VERSION 5.8 ;
BUSBITCHARS "[]" ;
DIVIDERCHAR "/" ;
UNITS
    DATABASE MICRONS 1000 ;
END UNITS

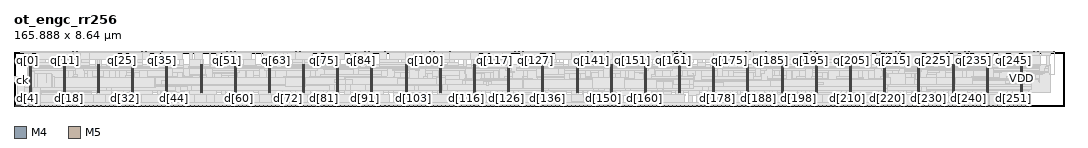
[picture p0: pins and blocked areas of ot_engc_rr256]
MACRO ot_engc_rr256
  FOREIGN ot_engc_rr256 0 0 ;
  CLASS BLOCK ;
  SIZE 165.888 BY 8.64 ;
  PIN ck
    DIRECTION INPUT ;
    USE SIGNAL ;
    PORT
      LAYER M4 ;
        RECT  0 4.032 0.084 4.056 ;
    END
  END ck
  PIN d[0]
    DIRECTION INPUT ;
    USE SIGNAL ;
    PORT
      LAYER M5 ;
        RECT  0.288 0 0.312 0.084 ;
    END
  END d[0]
  PIN d[100]
    DIRECTION INPUT ;
    USE SIGNAL ;
    PORT
      LAYER M5 ;
        RECT  61.152 0 61.176 0.084 ;
    END
  END d[100]
  PIN d[101]
    DIRECTION INPUT ;
    USE SIGNAL ;
    PORT
      LAYER M5 ;
        RECT  61.824 0 61.848 0.084 ;
    END
  END d[101]
  PIN d[102]
    DIRECTION INPUT ;
    USE SIGNAL ;
    PORT
      LAYER M5 ;
        RECT  62.448 0 62.472 0.084 ;
    END
  END d[102]
  PIN d[103]
    DIRECTION INPUT ;
    USE SIGNAL ;
    PORT
      LAYER M5 ;
        RECT  63.072 0 63.096 0.084 ;
    END
  END d[103]
  PIN d[104]
    DIRECTION INPUT ;
    USE SIGNAL ;
    PORT
      LAYER M5 ;
        RECT  63.744 0 63.768 0.084 ;
    END
  END d[104]
  PIN d[105]
    DIRECTION INPUT ;
    USE SIGNAL ;
    PORT
      LAYER M5 ;
        RECT  64.368 0 64.392 0.084 ;
    END
  END d[105]
  PIN d[106]
    DIRECTION INPUT ;
    USE SIGNAL ;
    PORT
      LAYER M5 ;
        RECT  64.992 0 65.016 0.084 ;
    END
  END d[106]
  PIN d[107]
    DIRECTION INPUT ;
    USE SIGNAL ;
    PORT
      LAYER M5 ;
        RECT  65.664 0 65.688 0.084 ;
    END
  END d[107]
  PIN d[108]
    DIRECTION INPUT ;
    USE SIGNAL ;
    PORT
      LAYER M5 ;
        RECT  66.288 0 66.312 0.084 ;
    END
  END d[108]
  PIN d[109]
    DIRECTION INPUT ;
    USE SIGNAL ;
    PORT
      LAYER M5 ;
        RECT  66.912 0 66.936 0.084 ;
    END
  END d[109]
  PIN d[10]
    DIRECTION INPUT ;
    USE SIGNAL ;
    PORT
      LAYER M5 ;
        RECT  3.504 0 3.528 0.084 ;
    END
  END d[10]
  PIN d[110]
    DIRECTION INPUT ;
    USE SIGNAL ;
    PORT
      LAYER M5 ;
        RECT  67.584 0 67.608 0.084 ;
    END
  END d[110]
  PIN d[111]
    DIRECTION INPUT ;
    USE SIGNAL ;
    PORT
      LAYER M5 ;
        RECT  68.208 0 68.232 0.084 ;
    END
  END d[111]
  PIN d[112]
    DIRECTION INPUT ;
    USE SIGNAL ;
    PORT
      LAYER M5 ;
        RECT  68.832 0 68.856 0.084 ;
    END
  END d[112]
  PIN d[113]
    DIRECTION INPUT ;
    USE SIGNAL ;
    PORT
      LAYER M5 ;
        RECT  69.504 0 69.528 0.084 ;
    END
  END d[113]
  PIN d[114]
    DIRECTION INPUT ;
    USE SIGNAL ;
    PORT
      LAYER M5 ;
        RECT  70.128 0 70.152 0.084 ;
    END
  END d[114]
  PIN d[115]
    DIRECTION INPUT ;
    USE SIGNAL ;
    PORT
      LAYER M5 ;
        RECT  70.752 0 70.776 0.084 ;
    END
  END d[115]
  PIN d[116]
    DIRECTION INPUT ;
    USE SIGNAL ;
    PORT
      LAYER M5 ;
        RECT  71.424 0 71.448 0.084 ;
    END
  END d[116]
  PIN d[117]
    DIRECTION INPUT ;
    USE SIGNAL ;
    PORT
      LAYER M5 ;
        RECT  72.048 0 72.072 0.084 ;
    END
  END d[117]
  PIN d[118]
    DIRECTION INPUT ;
    USE SIGNAL ;
    PORT
      LAYER M5 ;
        RECT  72.672 0 72.696 0.084 ;
    END
  END d[118]
  PIN d[119]
    DIRECTION INPUT ;
    USE SIGNAL ;
    PORT
      LAYER M5 ;
        RECT  73.344 0 73.368 0.084 ;
    END
  END d[119]
  PIN d[11]
    DIRECTION INPUT ;
    USE SIGNAL ;
    PORT
      LAYER M5 ;
        RECT  4.128 0 4.152 0.084 ;
    END
  END d[11]
  PIN d[120]
    DIRECTION INPUT ;
    USE SIGNAL ;
    PORT
      LAYER M5 ;
        RECT  73.968 0 73.992 0.084 ;
    END
  END d[120]
  PIN d[121]
    DIRECTION INPUT ;
    USE SIGNAL ;
    PORT
      LAYER M5 ;
        RECT  74.592 0 74.616 0.084 ;
    END
  END d[121]
  PIN d[122]
    DIRECTION INPUT ;
    USE SIGNAL ;
    PORT
      LAYER M5 ;
        RECT  75.264 0 75.288 0.084 ;
    END
  END d[122]
  PIN d[123]
    DIRECTION INPUT ;
    USE SIGNAL ;
    PORT
      LAYER M5 ;
        RECT  75.888 0 75.912 0.084 ;
    END
  END d[123]
  PIN d[124]
    DIRECTION INPUT ;
    USE SIGNAL ;
    PORT
      LAYER M5 ;
        RECT  76.512 0 76.536 0.084 ;
    END
  END d[124]
  PIN d[125]
    DIRECTION INPUT ;
    USE SIGNAL ;
    PORT
      LAYER M5 ;
        RECT  77.184 0 77.208 0.084 ;
    END
  END d[125]
  PIN d[126]
    DIRECTION INPUT ;
    USE SIGNAL ;
    PORT
      LAYER M5 ;
        RECT  77.808 0 77.832 0.084 ;
    END
  END d[126]
  PIN d[127]
    DIRECTION INPUT ;
    USE SIGNAL ;
    PORT
      LAYER M5 ;
        RECT  78.432 0 78.456 0.084 ;
    END
  END d[127]
  PIN d[128]
    DIRECTION INPUT ;
    USE SIGNAL ;
    PORT
      LAYER M5 ;
        RECT  79.104 0 79.128 0.084 ;
    END
  END d[128]
  PIN d[129]
    DIRECTION INPUT ;
    USE SIGNAL ;
    PORT
      LAYER M5 ;
        RECT  79.728 0 79.752 0.084 ;
    END
  END d[129]
  PIN d[12]
    DIRECTION INPUT ;
    USE SIGNAL ;
    PORT
      LAYER M5 ;
        RECT  4.8 0 4.824 0.084 ;
    END
  END d[12]
  PIN d[130]
    DIRECTION INPUT ;
    USE SIGNAL ;
    PORT
      LAYER M5 ;
        RECT  80.352 0 80.376 0.084 ;
    END
  END d[130]
  PIN d[131]
    DIRECTION INPUT ;
    USE SIGNAL ;
    PORT
      LAYER M5 ;
        RECT  81.024 0 81.048 0.084 ;
    END
  END d[131]
  PIN d[132]
    DIRECTION INPUT ;
    USE SIGNAL ;
    PORT
      LAYER M5 ;
        RECT  81.648 0 81.672 0.084 ;
    END
  END d[132]
  PIN d[133]
    DIRECTION INPUT ;
    USE SIGNAL ;
    PORT
      LAYER M5 ;
        RECT  82.272 0 82.296 0.084 ;
    END
  END d[133]
  PIN d[134]
    DIRECTION INPUT ;
    USE SIGNAL ;
    PORT
      LAYER M5 ;
        RECT  82.944 0 82.968 0.084 ;
    END
  END d[134]
  PIN d[135]
    DIRECTION INPUT ;
    USE SIGNAL ;
    PORT
      LAYER M5 ;
        RECT  83.568 0 83.592 0.084 ;
    END
  END d[135]
  PIN d[136]
    DIRECTION INPUT ;
    USE SIGNAL ;
    PORT
      LAYER M5 ;
        RECT  84.24 0 84.264 0.084 ;
    END
  END d[136]
  PIN d[137]
    DIRECTION INPUT ;
    USE SIGNAL ;
    PORT
      LAYER M5 ;
        RECT  84.864 0 84.888 0.084 ;
    END
  END d[137]
  PIN d[138]
    DIRECTION INPUT ;
    USE SIGNAL ;
    PORT
      LAYER M5 ;
        RECT  85.488 0 85.512 0.084 ;
    END
  END d[138]
  PIN d[139]
    DIRECTION INPUT ;
    USE SIGNAL ;
    PORT
      LAYER M5 ;
        RECT  86.16 0 86.184 0.084 ;
    END
  END d[139]
  PIN d[13]
    DIRECTION INPUT ;
    USE SIGNAL ;
    PORT
      LAYER M5 ;
        RECT  5.424 0 5.448 0.084 ;
    END
  END d[13]
  PIN d[140]
    DIRECTION INPUT ;
    USE SIGNAL ;
    PORT
      LAYER M5 ;
        RECT  86.784 0 86.808 0.084 ;
    END
  END d[140]
  PIN d[141]
    DIRECTION INPUT ;
    USE SIGNAL ;
    PORT
      LAYER M5 ;
        RECT  87.408 0 87.432 0.084 ;
    END
  END d[141]
  PIN d[142]
    DIRECTION INPUT ;
    USE SIGNAL ;
    PORT
      LAYER M5 ;
        RECT  88.08 0 88.104 0.084 ;
    END
  END d[142]
  PIN d[143]
    DIRECTION INPUT ;
    USE SIGNAL ;
    PORT
      LAYER M5 ;
        RECT  88.704 0 88.728 0.084 ;
    END
  END d[143]
  PIN d[144]
    DIRECTION INPUT ;
    USE SIGNAL ;
    PORT
      LAYER M5 ;
        RECT  89.328 0 89.352 0.084 ;
    END
  END d[144]
  PIN d[145]
    DIRECTION INPUT ;
    USE SIGNAL ;
    PORT
      LAYER M5 ;
        RECT  90 0 90.024 0.084 ;
    END
  END d[145]
  PIN d[146]
    DIRECTION INPUT ;
    USE SIGNAL ;
    PORT
      LAYER M5 ;
        RECT  90.624 0 90.648 0.084 ;
    END
  END d[146]
  PIN d[147]
    DIRECTION INPUT ;
    USE SIGNAL ;
    PORT
      LAYER M5 ;
        RECT  91.248 0 91.272 0.084 ;
    END
  END d[147]
  PIN d[148]
    DIRECTION INPUT ;
    USE SIGNAL ;
    PORT
      LAYER M5 ;
        RECT  91.92 0 91.944 0.084 ;
    END
  END d[148]
  PIN d[149]
    DIRECTION INPUT ;
    USE SIGNAL ;
    PORT
      LAYER M5 ;
        RECT  92.544 0 92.568 0.084 ;
    END
  END d[149]
  PIN d[14]
    DIRECTION INPUT ;
    USE SIGNAL ;
    PORT
      LAYER M5 ;
        RECT  6.048 0 6.072 0.084 ;
    END
  END d[14]
  PIN d[150]
    DIRECTION INPUT ;
    USE SIGNAL ;
    PORT
      LAYER M5 ;
        RECT  93.168 0 93.192 0.084 ;
    END
  END d[150]
  PIN d[151]
    DIRECTION INPUT ;
    USE SIGNAL ;
    PORT
      LAYER M5 ;
        RECT  93.84 0 93.864 0.084 ;
    END
  END d[151]
  PIN d[152]
    DIRECTION INPUT ;
    USE SIGNAL ;
    PORT
      LAYER M5 ;
        RECT  94.464 0 94.488 0.084 ;
    END
  END d[152]
  PIN d[153]
    DIRECTION INPUT ;
    USE SIGNAL ;
    PORT
      LAYER M5 ;
        RECT  95.088 0 95.112 0.084 ;
    END
  END d[153]
  PIN d[154]
    DIRECTION INPUT ;
    USE SIGNAL ;
    PORT
      LAYER M5 ;
        RECT  95.76 0 95.784 0.084 ;
    END
  END d[154]
  PIN d[155]
    DIRECTION INPUT ;
    USE SIGNAL ;
    PORT
      LAYER M5 ;
        RECT  96.384 0 96.408 0.084 ;
    END
  END d[155]
  PIN d[156]
    DIRECTION INPUT ;
    USE SIGNAL ;
    PORT
      LAYER M5 ;
        RECT  97.008 0 97.032 0.084 ;
    END
  END d[156]
  PIN d[157]
    DIRECTION INPUT ;
    USE SIGNAL ;
    PORT
      LAYER M5 ;
        RECT  97.68 0 97.704 0.084 ;
    END
  END d[157]
  PIN d[158]
    DIRECTION INPUT ;
    USE SIGNAL ;
    PORT
      LAYER M5 ;
        RECT  98.304 0 98.328 0.084 ;
    END
  END d[158]
  PIN d[159]
    DIRECTION INPUT ;
    USE SIGNAL ;
    PORT
      LAYER M5 ;
        RECT  98.976 0 99 0.084 ;
    END
  END d[159]
  PIN d[15]
    DIRECTION INPUT ;
    USE SIGNAL ;
    PORT
      LAYER M5 ;
        RECT  6.72 0 6.744 0.084 ;
    END
  END d[15]
  PIN d[160]
    DIRECTION INPUT ;
    USE SIGNAL ;
    PORT
      LAYER M5 ;
        RECT  99.552 0 99.576 0.084 ;
    END
  END d[160]
  PIN d[161]
    DIRECTION INPUT ;
    USE SIGNAL ;
    PORT
      LAYER M5 ;
        RECT  100.224 0 100.248 0.084 ;
    END
  END d[161]
  PIN d[162]
    DIRECTION INPUT ;
    USE SIGNAL ;
    PORT
      LAYER M5 ;
        RECT  100.848 0 100.872 0.084 ;
    END
  END d[162]
  PIN d[163]
    DIRECTION INPUT ;
    USE SIGNAL ;
    PORT
      LAYER M5 ;
        RECT  101.472 0 101.496 0.084 ;
    END
  END d[163]
  PIN d[164]
    DIRECTION INPUT ;
    USE SIGNAL ;
    PORT
      LAYER M5 ;
        RECT  102.144 0 102.168 0.084 ;
    END
  END d[164]
  PIN d[165]
    DIRECTION INPUT ;
    USE SIGNAL ;
    PORT
      LAYER M5 ;
        RECT  102.768 0 102.792 0.084 ;
    END
  END d[165]
  PIN d[166]
    DIRECTION INPUT ;
    USE SIGNAL ;
    PORT
      LAYER M5 ;
        RECT  103.392 0 103.416 0.084 ;
    END
  END d[166]
  PIN d[167]
    DIRECTION INPUT ;
    USE SIGNAL ;
    PORT
      LAYER M5 ;
        RECT  104.064 0 104.088 0.084 ;
    END
  END d[167]
  PIN d[168]
    DIRECTION INPUT ;
    USE SIGNAL ;
    PORT
      LAYER M5 ;
        RECT  104.688 0 104.712 0.084 ;
    END
  END d[168]
  PIN d[169]
    DIRECTION INPUT ;
    USE SIGNAL ;
    PORT
      LAYER M5 ;
        RECT  105.312 0 105.336 0.084 ;
    END
  END d[169]
  PIN d[16]
    DIRECTION INPUT ;
    USE SIGNAL ;
    PORT
      LAYER M5 ;
        RECT  7.344 0 7.368 0.084 ;
    END
  END d[16]
  PIN d[170]
    DIRECTION INPUT ;
    USE SIGNAL ;
    PORT
      LAYER M5 ;
        RECT  105.984 0 106.008 0.084 ;
    END
  END d[170]
  PIN d[171]
    DIRECTION INPUT ;
    USE SIGNAL ;
    PORT
      LAYER M5 ;
        RECT  106.608 0 106.632 0.084 ;
    END
  END d[171]
  PIN d[172]
    DIRECTION INPUT ;
    USE SIGNAL ;
    PORT
      LAYER M5 ;
        RECT  107.232 0 107.256 0.084 ;
    END
  END d[172]
  PIN d[173]
    DIRECTION INPUT ;
    USE SIGNAL ;
    PORT
      LAYER M5 ;
        RECT  107.904 0 107.928 0.084 ;
    END
  END d[173]
  PIN d[174]
    DIRECTION INPUT ;
    USE SIGNAL ;
    PORT
      LAYER M5 ;
        RECT  108.528 0 108.552 0.084 ;
    END
  END d[174]
  PIN d[175]
    DIRECTION INPUT ;
    USE SIGNAL ;
    PORT
      LAYER M5 ;
        RECT  109.152 0 109.176 0.084 ;
    END
  END d[175]
  PIN d[176]
    DIRECTION INPUT ;
    USE SIGNAL ;
    PORT
      LAYER M5 ;
        RECT  109.824 0 109.848 0.084 ;
    END
  END d[176]
  PIN d[177]
    DIRECTION INPUT ;
    USE SIGNAL ;
    PORT
      LAYER M5 ;
        RECT  110.448 0 110.472 0.084 ;
    END
  END d[177]
  PIN d[178]
    DIRECTION INPUT ;
    USE SIGNAL ;
    PORT
      LAYER M5 ;
        RECT  111.168 0 111.192 0.084 ;
    END
  END d[178]
  PIN d[179]
    DIRECTION INPUT ;
    USE SIGNAL ;
    PORT
      LAYER M5 ;
        RECT  111.792 0 111.816 0.084 ;
    END
  END d[179]
  PIN d[17]
    DIRECTION INPUT ;
    USE SIGNAL ;
    PORT
      LAYER M5 ;
        RECT  7.968 0 7.992 0.084 ;
    END
  END d[17]
  PIN d[180]
    DIRECTION INPUT ;
    USE SIGNAL ;
    PORT
      LAYER M5 ;
        RECT  112.416 0 112.44 0.084 ;
    END
  END d[180]
  PIN d[181]
    DIRECTION INPUT ;
    USE SIGNAL ;
    PORT
      LAYER M5 ;
        RECT  113.088 0 113.112 0.084 ;
    END
  END d[181]
  PIN d[182]
    DIRECTION INPUT ;
    USE SIGNAL ;
    PORT
      LAYER M5 ;
        RECT  113.712 0 113.736 0.084 ;
    END
  END d[182]
  PIN d[183]
    DIRECTION INPUT ;
    USE SIGNAL ;
    PORT
      LAYER M5 ;
        RECT  114.336 0 114.36 0.084 ;
    END
  END d[183]
  PIN d[184]
    DIRECTION INPUT ;
    USE SIGNAL ;
    PORT
      LAYER M5 ;
        RECT  115.008 0 115.032 0.084 ;
    END
  END d[184]
  PIN d[185]
    DIRECTION INPUT ;
    USE SIGNAL ;
    PORT
      LAYER M5 ;
        RECT  115.632 0 115.656 0.084 ;
    END
  END d[185]
  PIN d[186]
    DIRECTION INPUT ;
    USE SIGNAL ;
    PORT
      LAYER M5 ;
        RECT  116.256 0 116.28 0.084 ;
    END
  END d[186]
  PIN d[187]
    DIRECTION INPUT ;
    USE SIGNAL ;
    PORT
      LAYER M5 ;
        RECT  116.928 0 116.952 0.084 ;
    END
  END d[187]
  PIN d[188]
    DIRECTION INPUT ;
    USE SIGNAL ;
    PORT
      LAYER M5 ;
        RECT  117.552 0 117.576 0.084 ;
    END
  END d[188]
  PIN d[189]
    DIRECTION INPUT ;
    USE SIGNAL ;
    PORT
      LAYER M5 ;
        RECT  118.176 0 118.2 0.084 ;
    END
  END d[189]
  PIN d[18]
    DIRECTION INPUT ;
    USE SIGNAL ;
    PORT
      LAYER M5 ;
        RECT  8.64 0 8.664 0.084 ;
    END
  END d[18]
  PIN d[190]
    DIRECTION INPUT ;
    USE SIGNAL ;
    PORT
      LAYER M5 ;
        RECT  118.848 0 118.872 0.084 ;
    END
  END d[190]
  PIN d[191]
    DIRECTION INPUT ;
    USE SIGNAL ;
    PORT
      LAYER M5 ;
        RECT  119.472 0 119.496 0.084 ;
    END
  END d[191]
  PIN d[192]
    DIRECTION INPUT ;
    USE SIGNAL ;
    PORT
      LAYER M5 ;
        RECT  120.096 0 120.12 0.084 ;
    END
  END d[192]
  PIN d[193]
    DIRECTION INPUT ;
    USE SIGNAL ;
    PORT
      LAYER M5 ;
        RECT  120.72 0 120.744 0.084 ;
    END
  END d[193]
  PIN d[194]
    DIRECTION INPUT ;
    USE SIGNAL ;
    PORT
      LAYER M5 ;
        RECT  121.392 0 121.416 0.084 ;
    END
  END d[194]
  PIN d[195]
    DIRECTION INPUT ;
    USE SIGNAL ;
    PORT
      LAYER M5 ;
        RECT  122.016 0 122.04 0.084 ;
    END
  END d[195]
  PIN d[196]
    DIRECTION INPUT ;
    USE SIGNAL ;
    PORT
      LAYER M5 ;
        RECT  122.64 0 122.664 0.084 ;
    END
  END d[196]
  PIN d[197]
    DIRECTION INPUT ;
    USE SIGNAL ;
    PORT
      LAYER M5 ;
        RECT  123.312 0 123.336 0.084 ;
    END
  END d[197]
  PIN d[198]
    DIRECTION INPUT ;
    USE SIGNAL ;
    PORT
      LAYER M5 ;
        RECT  123.936 0 123.96 0.084 ;
    END
  END d[198]
  PIN d[199]
    DIRECTION INPUT ;
    USE SIGNAL ;
    PORT
      LAYER M5 ;
        RECT  124.56 0 124.584 0.084 ;
    END
  END d[199]
  PIN d[19]
    DIRECTION INPUT ;
    USE SIGNAL ;
    PORT
      LAYER M5 ;
        RECT  9.264 0 9.288 0.084 ;
    END
  END d[19]
  PIN d[1]
    DIRECTION INPUT ;
    USE SIGNAL ;
    PORT
      LAYER M5 ;
        RECT  0.384 0 0.408 0.084 ;
    END
  END d[1]
  PIN d[200]
    DIRECTION INPUT ;
    USE SIGNAL ;
    PORT
      LAYER M5 ;
        RECT  125.232 0 125.256 0.084 ;
    END
  END d[200]
  PIN d[201]
    DIRECTION INPUT ;
    USE SIGNAL ;
    PORT
      LAYER M5 ;
        RECT  125.856 0 125.88 0.084 ;
    END
  END d[201]
  PIN d[202]
    DIRECTION INPUT ;
    USE SIGNAL ;
    PORT
      LAYER M5 ;
        RECT  126.48 0 126.504 0.084 ;
    END
  END d[202]
  PIN d[203]
    DIRECTION INPUT ;
    USE SIGNAL ;
    PORT
      LAYER M5 ;
        RECT  127.152 0 127.176 0.084 ;
    END
  END d[203]
  PIN d[204]
    DIRECTION INPUT ;
    USE SIGNAL ;
    PORT
      LAYER M5 ;
        RECT  127.776 0 127.8 0.084 ;
    END
  END d[204]
  PIN d[205]
    DIRECTION INPUT ;
    USE SIGNAL ;
    PORT
      LAYER M5 ;
        RECT  128.4 0 128.424 0.084 ;
    END
  END d[205]
  PIN d[206]
    DIRECTION INPUT ;
    USE SIGNAL ;
    PORT
      LAYER M5 ;
        RECT  129.072 0 129.096 0.084 ;
    END
  END d[206]
  PIN d[207]
    DIRECTION INPUT ;
    USE SIGNAL ;
    PORT
      LAYER M5 ;
        RECT  129.696 0 129.72 0.084 ;
    END
  END d[207]
  PIN d[208]
    DIRECTION INPUT ;
    USE SIGNAL ;
    PORT
      LAYER M5 ;
        RECT  130.32 0 130.344 0.084 ;
    END
  END d[208]
  PIN d[209]
    DIRECTION INPUT ;
    USE SIGNAL ;
    PORT
      LAYER M5 ;
        RECT  130.992 0 131.016 0.084 ;
    END
  END d[209]
  PIN d[20]
    DIRECTION INPUT ;
    USE SIGNAL ;
    PORT
      LAYER M5 ;
        RECT  9.888 0 9.912 0.084 ;
    END
  END d[20]
  PIN d[210]
    DIRECTION INPUT ;
    USE SIGNAL ;
    PORT
      LAYER M5 ;
        RECT  131.616 0 131.64 0.084 ;
    END
  END d[210]
  PIN d[211]
    DIRECTION INPUT ;
    USE SIGNAL ;
    PORT
      LAYER M5 ;
        RECT  132.288 0 132.312 0.084 ;
    END
  END d[211]
  PIN d[212]
    DIRECTION INPUT ;
    USE SIGNAL ;
    PORT
      LAYER M5 ;
        RECT  132.912 0 132.936 0.084 ;
    END
  END d[212]
  PIN d[213]
    DIRECTION INPUT ;
    USE SIGNAL ;
    PORT
      LAYER M5 ;
        RECT  133.536 0 133.56 0.084 ;
    END
  END d[213]
  PIN d[214]
    DIRECTION INPUT ;
    USE SIGNAL ;
    PORT
      LAYER M5 ;
        RECT  134.208 0 134.232 0.084 ;
    END
  END d[214]
  PIN d[215]
    DIRECTION INPUT ;
    USE SIGNAL ;
    PORT
      LAYER M5 ;
        RECT  134.832 0 134.856 0.084 ;
    END
  END d[215]
  PIN d[216]
    DIRECTION INPUT ;
    USE SIGNAL ;
    PORT
      LAYER M5 ;
        RECT  135.456 0 135.48 0.084 ;
    END
  END d[216]
  PIN d[217]
    DIRECTION INPUT ;
    USE SIGNAL ;
    PORT
      LAYER M5 ;
        RECT  136.128 0 136.152 0.084 ;
    END
  END d[217]
  PIN d[218]
    DIRECTION INPUT ;
    USE SIGNAL ;
    PORT
      LAYER M5 ;
        RECT  136.752 0 136.776 0.084 ;
    END
  END d[218]
  PIN d[219]
    DIRECTION INPUT ;
    USE SIGNAL ;
    PORT
      LAYER M5 ;
        RECT  137.376 0 137.4 0.084 ;
    END
  END d[219]
  PIN d[21]
    DIRECTION INPUT ;
    USE SIGNAL ;
    PORT
      LAYER M5 ;
        RECT  10.56 0 10.584 0.084 ;
    END
  END d[21]
  PIN d[220]
    DIRECTION INPUT ;
    USE SIGNAL ;
    PORT
      LAYER M5 ;
        RECT  138.048 0 138.072 0.084 ;
    END
  END d[220]
  PIN d[221]
    DIRECTION INPUT ;
    USE SIGNAL ;
    PORT
      LAYER M5 ;
        RECT  138.672 0 138.696 0.084 ;
    END
  END d[221]
  PIN d[222]
    DIRECTION INPUT ;
    USE SIGNAL ;
    PORT
      LAYER M5 ;
        RECT  139.296 0 139.32 0.084 ;
    END
  END d[222]
  PIN d[223]
    DIRECTION INPUT ;
    USE SIGNAL ;
    PORT
      LAYER M5 ;
        RECT  139.968 0 139.992 0.084 ;
    END
  END d[223]
  PIN d[224]
    DIRECTION INPUT ;
    USE SIGNAL ;
    PORT
      LAYER M5 ;
        RECT  140.592 0 140.616 0.084 ;
    END
  END d[224]
  PIN d[225]
    DIRECTION INPUT ;
    USE SIGNAL ;
    PORT
      LAYER M5 ;
        RECT  141.216 0 141.24 0.084 ;
    END
  END d[225]
  PIN d[226]
    DIRECTION INPUT ;
    USE SIGNAL ;
    PORT
      LAYER M5 ;
        RECT  141.888 0 141.912 0.084 ;
    END
  END d[226]
  PIN d[227]
    DIRECTION INPUT ;
    USE SIGNAL ;
    PORT
      LAYER M5 ;
        RECT  142.512 0 142.536 0.084 ;
    END
  END d[227]
  PIN d[228]
    DIRECTION INPUT ;
    USE SIGNAL ;
    PORT
      LAYER M5 ;
        RECT  143.136 0 143.16 0.084 ;
    END
  END d[228]
  PIN d[229]
    DIRECTION INPUT ;
    USE SIGNAL ;
    PORT
      LAYER M5 ;
        RECT  143.808 0 143.832 0.084 ;
    END
  END d[229]
  PIN d[22]
    DIRECTION INPUT ;
    USE SIGNAL ;
    PORT
      LAYER M5 ;
        RECT  11.184 0 11.208 0.084 ;
    END
  END d[22]
  PIN d[230]
    DIRECTION INPUT ;
    USE SIGNAL ;
    PORT
      LAYER M5 ;
        RECT  144.432 0 144.456 0.084 ;
    END
  END d[230]
  PIN d[231]
    DIRECTION INPUT ;
    USE SIGNAL ;
    PORT
      LAYER M5 ;
        RECT  145.056 0 145.08 0.084 ;
    END
  END d[231]
  PIN d[232]
    DIRECTION INPUT ;
    USE SIGNAL ;
    PORT
      LAYER M5 ;
        RECT  145.728 0 145.752 0.084 ;
    END
  END d[232]
  PIN d[233]
    DIRECTION INPUT ;
    USE SIGNAL ;
    PORT
      LAYER M5 ;
        RECT  146.352 0 146.376 0.084 ;
    END
  END d[233]
  PIN d[234]
    DIRECTION INPUT ;
    USE SIGNAL ;
    PORT
      LAYER M5 ;
        RECT  146.976 0 147 0.084 ;
    END
  END d[234]
  PIN d[235]
    DIRECTION INPUT ;
    USE SIGNAL ;
    PORT
      LAYER M5 ;
        RECT  147.648 0 147.672 0.084 ;
    END
  END d[235]
  PIN d[236]
    DIRECTION INPUT ;
    USE SIGNAL ;
    PORT
      LAYER M5 ;
        RECT  148.272 0 148.296 0.084 ;
    END
  END d[236]
  PIN d[237]
    DIRECTION INPUT ;
    USE SIGNAL ;
    PORT
      LAYER M5 ;
        RECT  148.896 0 148.92 0.084 ;
    END
  END d[237]
  PIN d[238]
    DIRECTION INPUT ;
    USE SIGNAL ;
    PORT
      LAYER M5 ;
        RECT  149.568 0 149.592 0.084 ;
    END
  END d[238]
  PIN d[239]
    DIRECTION INPUT ;
    USE SIGNAL ;
    PORT
      LAYER M5 ;
        RECT  150.192 0 150.216 0.084 ;
    END
  END d[239]
  PIN d[23]
    DIRECTION INPUT ;
    USE SIGNAL ;
    PORT
      LAYER M5 ;
        RECT  11.808 0 11.832 0.084 ;
    END
  END d[23]
  PIN d[240]
    DIRECTION INPUT ;
    USE SIGNAL ;
    PORT
      LAYER M5 ;
        RECT  150.816 0 150.84 0.084 ;
    END
  END d[240]
  PIN d[241]
    DIRECTION INPUT ;
    USE SIGNAL ;
    PORT
      LAYER M5 ;
        RECT  151.488 0 151.512 0.084 ;
    END
  END d[241]
  PIN d[242]
    DIRECTION INPUT ;
    USE SIGNAL ;
    PORT
      LAYER M5 ;
        RECT  152.112 0 152.136 0.084 ;
    END
  END d[242]
  PIN d[243]
    DIRECTION INPUT ;
    USE SIGNAL ;
    PORT
      LAYER M5 ;
        RECT  152.736 0 152.76 0.084 ;
    END
  END d[243]
  PIN d[244]
    DIRECTION INPUT ;
    USE SIGNAL ;
    PORT
      LAYER M5 ;
        RECT  153.408 0 153.432 0.084 ;
    END
  END d[244]
  PIN d[245]
    DIRECTION INPUT ;
    USE SIGNAL ;
    PORT
      LAYER M5 ;
        RECT  154.032 0 154.056 0.084 ;
    END
  END d[245]
  PIN d[246]
    DIRECTION INPUT ;
    USE SIGNAL ;
    PORT
      LAYER M5 ;
        RECT  154.656 0 154.68 0.084 ;
    END
  END d[246]
  PIN d[247]
    DIRECTION INPUT ;
    USE SIGNAL ;
    PORT
      LAYER M5 ;
        RECT  155.328 0 155.352 0.084 ;
    END
  END d[247]
  PIN d[248]
    DIRECTION INPUT ;
    USE SIGNAL ;
    PORT
      LAYER M5 ;
        RECT  155.952 0 155.976 0.084 ;
    END
  END d[248]
  PIN d[249]
    DIRECTION INPUT ;
    USE SIGNAL ;
    PORT
      LAYER M5 ;
        RECT  156.576 0 156.6 0.084 ;
    END
  END d[249]
  PIN d[24]
    DIRECTION INPUT ;
    USE SIGNAL ;
    PORT
      LAYER M5 ;
        RECT  12.48 0 12.504 0.084 ;
    END
  END d[24]
  PIN d[250]
    DIRECTION INPUT ;
    USE SIGNAL ;
    PORT
      LAYER M5 ;
        RECT  157.248 0 157.272 0.084 ;
    END
  END d[250]
  PIN d[251]
    DIRECTION INPUT ;
    USE SIGNAL ;
    PORT
      LAYER M5 ;
        RECT  157.872 0 157.896 0.084 ;
    END
  END d[251]
  PIN d[252]
    DIRECTION INPUT ;
    USE SIGNAL ;
    PORT
      LAYER M5 ;
        RECT  158.496 0 158.52 0.084 ;
    END
  END d[252]
  PIN d[253]
    DIRECTION INPUT ;
    USE SIGNAL ;
    PORT
      LAYER M5 ;
        RECT  159.168 0 159.192 0.084 ;
    END
  END d[253]
  PIN d[254]
    DIRECTION INPUT ;
    USE SIGNAL ;
    PORT
      LAYER M5 ;
        RECT  159.792 0 159.816 0.084 ;
    END
  END d[254]
  PIN d[255]
    DIRECTION INPUT ;
    USE SIGNAL ;
    PORT
      LAYER M5 ;
        RECT  160.416 0 160.44 0.084 ;
    END
  END d[255]
  PIN d[25]
    DIRECTION INPUT ;
    USE SIGNAL ;
    PORT
      LAYER M5 ;
        RECT  13.104 0 13.128 0.084 ;
    END
  END d[25]
  PIN d[26]
    DIRECTION INPUT ;
    USE SIGNAL ;
    PORT
      LAYER M5 ;
        RECT  13.728 0 13.752 0.084 ;
    END
  END d[26]
  PIN d[27]
    DIRECTION INPUT ;
    USE SIGNAL ;
    PORT
      LAYER M5 ;
        RECT  14.4 0 14.424 0.084 ;
    END
  END d[27]
  PIN d[28]
    DIRECTION INPUT ;
    USE SIGNAL ;
    PORT
      LAYER M5 ;
        RECT  15.024 0 15.048 0.084 ;
    END
  END d[28]
  PIN d[29]
    DIRECTION INPUT ;
    USE SIGNAL ;
    PORT
      LAYER M5 ;
        RECT  15.648 0 15.672 0.084 ;
    END
  END d[29]
  PIN d[2]
    DIRECTION INPUT ;
    USE SIGNAL ;
    PORT
      LAYER M5 ;
        RECT  0.48 0 0.504 0.084 ;
    END
  END d[2]
  PIN d[30]
    DIRECTION INPUT ;
    USE SIGNAL ;
    PORT
      LAYER M5 ;
        RECT  16.32 0 16.344 0.084 ;
    END
  END d[30]
  PIN d[31]
    DIRECTION INPUT ;
    USE SIGNAL ;
    PORT
      LAYER M5 ;
        RECT  16.944 0 16.968 0.084 ;
    END
  END d[31]
  PIN d[32]
    DIRECTION INPUT ;
    USE SIGNAL ;
    PORT
      LAYER M5 ;
        RECT  17.568 0 17.592 0.084 ;
    END
  END d[32]
  PIN d[33]
    DIRECTION INPUT ;
    USE SIGNAL ;
    PORT
      LAYER M5 ;
        RECT  18.24 0 18.264 0.084 ;
    END
  END d[33]
  PIN d[34]
    DIRECTION INPUT ;
    USE SIGNAL ;
    PORT
      LAYER M5 ;
        RECT  18.864 0 18.888 0.084 ;
    END
  END d[34]
  PIN d[35]
    DIRECTION INPUT ;
    USE SIGNAL ;
    PORT
      LAYER M5 ;
        RECT  19.488 0 19.512 0.084 ;
    END
  END d[35]
  PIN d[36]
    DIRECTION INPUT ;
    USE SIGNAL ;
    PORT
      LAYER M5 ;
        RECT  20.16 0 20.184 0.084 ;
    END
  END d[36]
  PIN d[37]
    DIRECTION INPUT ;
    USE SIGNAL ;
    PORT
      LAYER M5 ;
        RECT  20.784 0 20.808 0.084 ;
    END
  END d[37]
  PIN d[38]
    DIRECTION INPUT ;
    USE SIGNAL ;
    PORT
      LAYER M5 ;
        RECT  21.408 0 21.432 0.084 ;
    END
  END d[38]
  PIN d[39]
    DIRECTION INPUT ;
    USE SIGNAL ;
    PORT
      LAYER M5 ;
        RECT  22.08 0 22.104 0.084 ;
    END
  END d[39]
  PIN d[3]
    DIRECTION INPUT ;
    USE SIGNAL ;
    PORT
      LAYER M5 ;
        RECT  0.576 0 0.6 0.084 ;
    END
  END d[3]
  PIN d[40]
    DIRECTION INPUT ;
    USE SIGNAL ;
    PORT
      LAYER M5 ;
        RECT  22.704 0 22.728 0.084 ;
    END
  END d[40]
  PIN d[41]
    DIRECTION INPUT ;
    USE SIGNAL ;
    PORT
      LAYER M5 ;
        RECT  23.328 0 23.352 0.084 ;
    END
  END d[41]
  PIN d[42]
    DIRECTION INPUT ;
    USE SIGNAL ;
    PORT
      LAYER M5 ;
        RECT  24 0 24.024 0.084 ;
    END
  END d[42]
  PIN d[43]
    DIRECTION INPUT ;
    USE SIGNAL ;
    PORT
      LAYER M5 ;
        RECT  24.624 0 24.648 0.084 ;
    END
  END d[43]
  PIN d[44]
    DIRECTION INPUT ;
    USE SIGNAL ;
    PORT
      LAYER M5 ;
        RECT  25.248 0 25.272 0.084 ;
    END
  END d[44]
  PIN d[45]
    DIRECTION INPUT ;
    USE SIGNAL ;
    PORT
      LAYER M5 ;
        RECT  25.92 0 25.944 0.084 ;
    END
  END d[45]
  PIN d[46]
    DIRECTION INPUT ;
    USE SIGNAL ;
    PORT
      LAYER M5 ;
        RECT  26.544 0 26.568 0.084 ;
    END
  END d[46]
  PIN d[47]
    DIRECTION INPUT ;
    USE SIGNAL ;
    PORT
      LAYER M5 ;
        RECT  27.168 0 27.192 0.084 ;
    END
  END d[47]
  PIN d[48]
    DIRECTION INPUT ;
    USE SIGNAL ;
    PORT
      LAYER M5 ;
        RECT  27.84 0 27.864 0.084 ;
    END
  END d[48]
  PIN d[49]
    DIRECTION INPUT ;
    USE SIGNAL ;
    PORT
      LAYER M5 ;
        RECT  28.464 0 28.488 0.084 ;
    END
  END d[49]
  PIN d[4]
    DIRECTION INPUT ;
    USE SIGNAL ;
    PORT
      LAYER M5 ;
        RECT  0.672 0 0.696 0.084 ;
    END
  END d[4]
  PIN d[50]
    DIRECTION INPUT ;
    USE SIGNAL ;
    PORT
      LAYER M5 ;
        RECT  29.088 0 29.112 0.084 ;
    END
  END d[50]
  PIN d[51]
    DIRECTION INPUT ;
    USE SIGNAL ;
    PORT
      LAYER M5 ;
        RECT  29.76 0 29.784 0.084 ;
    END
  END d[51]
  PIN d[52]
    DIRECTION INPUT ;
    USE SIGNAL ;
    PORT
      LAYER M5 ;
        RECT  30.384 0 30.408 0.084 ;
    END
  END d[52]
  PIN d[53]
    DIRECTION INPUT ;
    USE SIGNAL ;
    PORT
      LAYER M5 ;
        RECT  31.008 0 31.032 0.084 ;
    END
  END d[53]
  PIN d[54]
    DIRECTION INPUT ;
    USE SIGNAL ;
    PORT
      LAYER M5 ;
        RECT  31.68 0 31.704 0.084 ;
    END
  END d[54]
  PIN d[55]
    DIRECTION INPUT ;
    USE SIGNAL ;
    PORT
      LAYER M5 ;
        RECT  32.304 0 32.328 0.084 ;
    END
  END d[55]
  PIN d[56]
    DIRECTION INPUT ;
    USE SIGNAL ;
    PORT
      LAYER M5 ;
        RECT  32.928 0 32.952 0.084 ;
    END
  END d[56]
  PIN d[57]
    DIRECTION INPUT ;
    USE SIGNAL ;
    PORT
      LAYER M5 ;
        RECT  33.6 0 33.624 0.084 ;
    END
  END d[57]
  PIN d[58]
    DIRECTION INPUT ;
    USE SIGNAL ;
    PORT
      LAYER M5 ;
        RECT  34.224 0 34.248 0.084 ;
    END
  END d[58]
  PIN d[59]
    DIRECTION INPUT ;
    USE SIGNAL ;
    PORT
      LAYER M5 ;
        RECT  34.848 0 34.872 0.084 ;
    END
  END d[59]
  PIN d[5]
    DIRECTION INPUT ;
    USE SIGNAL ;
    PORT
      LAYER M5 ;
        RECT  0.768 0 0.792 0.084 ;
    END
  END d[5]
  PIN d[60]
    DIRECTION INPUT ;
    USE SIGNAL ;
    PORT
      LAYER M5 ;
        RECT  35.52 0 35.544 0.084 ;
    END
  END d[60]
  PIN d[61]
    DIRECTION INPUT ;
    USE SIGNAL ;
    PORT
      LAYER M5 ;
        RECT  36.144 0 36.168 0.084 ;
    END
  END d[61]
  PIN d[62]
    DIRECTION INPUT ;
    USE SIGNAL ;
    PORT
      LAYER M5 ;
        RECT  36.768 0 36.792 0.084 ;
    END
  END d[62]
  PIN d[63]
    DIRECTION INPUT ;
    USE SIGNAL ;
    PORT
      LAYER M5 ;
        RECT  37.44 0 37.464 0.084 ;
    END
  END d[63]
  PIN d[64]
    DIRECTION INPUT ;
    USE SIGNAL ;
    PORT
      LAYER M5 ;
        RECT  38.112 0 38.136 0.084 ;
    END
  END d[64]
  PIN d[65]
    DIRECTION INPUT ;
    USE SIGNAL ;
    PORT
      LAYER M5 ;
        RECT  38.736 0 38.76 0.084 ;
    END
  END d[65]
  PIN d[66]
    DIRECTION INPUT ;
    USE SIGNAL ;
    PORT
      LAYER M5 ;
        RECT  39.36 0 39.384 0.084 ;
    END
  END d[66]
  PIN d[67]
    DIRECTION INPUT ;
    USE SIGNAL ;
    PORT
      LAYER M5 ;
        RECT  40.032 0 40.056 0.084 ;
    END
  END d[67]
  PIN d[68]
    DIRECTION INPUT ;
    USE SIGNAL ;
    PORT
      LAYER M5 ;
        RECT  40.656 0 40.68 0.084 ;
    END
  END d[68]
  PIN d[69]
    DIRECTION INPUT ;
    USE SIGNAL ;
    PORT
      LAYER M5 ;
        RECT  41.28 0 41.304 0.084 ;
    END
  END d[69]
  PIN d[6]
    DIRECTION INPUT ;
    USE SIGNAL ;
    PORT
      LAYER M5 ;
        RECT  0.96 0 0.984 0.084 ;
    END
  END d[6]
  PIN d[70]
    DIRECTION INPUT ;
    USE SIGNAL ;
    PORT
      LAYER M5 ;
        RECT  41.952 0 41.976 0.084 ;
    END
  END d[70]
  PIN d[71]
    DIRECTION INPUT ;
    USE SIGNAL ;
    PORT
      LAYER M5 ;
        RECT  42.576 0 42.6 0.084 ;
    END
  END d[71]
  PIN d[72]
    DIRECTION INPUT ;
    USE SIGNAL ;
    PORT
      LAYER M5 ;
        RECT  43.2 0 43.224 0.084 ;
    END
  END d[72]
  PIN d[73]
    DIRECTION INPUT ;
    USE SIGNAL ;
    PORT
      LAYER M5 ;
        RECT  43.872 0 43.896 0.084 ;
    END
  END d[73]
  PIN d[74]
    DIRECTION INPUT ;
    USE SIGNAL ;
    PORT
      LAYER M5 ;
        RECT  44.496 0 44.52 0.084 ;
    END
  END d[74]
  PIN d[75]
    DIRECTION INPUT ;
    USE SIGNAL ;
    PORT
      LAYER M5 ;
        RECT  45.12 0 45.144 0.084 ;
    END
  END d[75]
  PIN d[76]
    DIRECTION INPUT ;
    USE SIGNAL ;
    PORT
      LAYER M5 ;
        RECT  45.792 0 45.816 0.084 ;
    END
  END d[76]
  PIN d[77]
    DIRECTION INPUT ;
    USE SIGNAL ;
    PORT
      LAYER M5 ;
        RECT  46.416 0 46.44 0.084 ;
    END
  END d[77]
  PIN d[78]
    DIRECTION INPUT ;
    USE SIGNAL ;
    PORT
      LAYER M5 ;
        RECT  47.04 0 47.064 0.084 ;
    END
  END d[78]
  PIN d[79]
    DIRECTION INPUT ;
    USE SIGNAL ;
    PORT
      LAYER M5 ;
        RECT  47.712 0 47.736 0.084 ;
    END
  END d[79]
  PIN d[7]
    DIRECTION INPUT ;
    USE SIGNAL ;
    PORT
      LAYER M5 ;
        RECT  1.584 0 1.608 0.084 ;
    END
  END d[7]
  PIN d[80]
    DIRECTION INPUT ;
    USE SIGNAL ;
    PORT
      LAYER M5 ;
        RECT  48.336 0 48.36 0.084 ;
    END
  END d[80]
  PIN d[81]
    DIRECTION INPUT ;
    USE SIGNAL ;
    PORT
      LAYER M5 ;
        RECT  48.96 0 48.984 0.084 ;
    END
  END d[81]
  PIN d[82]
    DIRECTION INPUT ;
    USE SIGNAL ;
    PORT
      LAYER M5 ;
        RECT  49.632 0 49.656 0.084 ;
    END
  END d[82]
  PIN d[83]
    DIRECTION INPUT ;
    USE SIGNAL ;
    PORT
      LAYER M5 ;
        RECT  50.256 0 50.28 0.084 ;
    END
  END d[83]
  PIN d[84]
    DIRECTION INPUT ;
    USE SIGNAL ;
    PORT
      LAYER M5 ;
        RECT  50.928 0 50.952 0.084 ;
    END
  END d[84]
  PIN d[85]
    DIRECTION INPUT ;
    USE SIGNAL ;
    PORT
      LAYER M5 ;
        RECT  51.552 0 51.576 0.084 ;
    END
  END d[85]
  PIN d[86]
    DIRECTION INPUT ;
    USE SIGNAL ;
    PORT
      LAYER M5 ;
        RECT  52.176 0 52.2 0.084 ;
    END
  END d[86]
  PIN d[87]
    DIRECTION INPUT ;
    USE SIGNAL ;
    PORT
      LAYER M5 ;
        RECT  52.848 0 52.872 0.084 ;
    END
  END d[87]
  PIN d[88]
    DIRECTION INPUT ;
    USE SIGNAL ;
    PORT
      LAYER M5 ;
        RECT  53.472 0 53.496 0.084 ;
    END
  END d[88]
  PIN d[89]
    DIRECTION INPUT ;
    USE SIGNAL ;
    PORT
      LAYER M5 ;
        RECT  54.096 0 54.12 0.084 ;
    END
  END d[89]
  PIN d[8]
    DIRECTION INPUT ;
    USE SIGNAL ;
    PORT
      LAYER M5 ;
        RECT  2.208 0 2.232 0.084 ;
    END
  END d[8]
  PIN d[90]
    DIRECTION INPUT ;
    USE SIGNAL ;
    PORT
      LAYER M5 ;
        RECT  54.768 0 54.792 0.084 ;
    END
  END d[90]
  PIN d[91]
    DIRECTION INPUT ;
    USE SIGNAL ;
    PORT
      LAYER M5 ;
        RECT  55.392 0 55.416 0.084 ;
    END
  END d[91]
  PIN d[92]
    DIRECTION INPUT ;
    USE SIGNAL ;
    PORT
      LAYER M5 ;
        RECT  56.016 0 56.04 0.084 ;
    END
  END d[92]
  PIN d[93]
    DIRECTION INPUT ;
    USE SIGNAL ;
    PORT
      LAYER M5 ;
        RECT  56.688 0 56.712 0.084 ;
    END
  END d[93]
  PIN d[94]
    DIRECTION INPUT ;
    USE SIGNAL ;
    PORT
      LAYER M5 ;
        RECT  57.312 0 57.336 0.084 ;
    END
  END d[94]
  PIN d[95]
    DIRECTION INPUT ;
    USE SIGNAL ;
    PORT
      LAYER M5 ;
        RECT  57.936 0 57.96 0.084 ;
    END
  END d[95]
  PIN d[96]
    DIRECTION INPUT ;
    USE SIGNAL ;
    PORT
      LAYER M5 ;
        RECT  58.608 0 58.632 0.084 ;
    END
  END d[96]
  PIN d[97]
    DIRECTION INPUT ;
    USE SIGNAL ;
    PORT
      LAYER M5 ;
        RECT  59.232 0 59.256 0.084 ;
    END
  END d[97]
  PIN d[98]
    DIRECTION INPUT ;
    USE SIGNAL ;
    PORT
      LAYER M5 ;
        RECT  59.904 0 59.928 0.084 ;
    END
  END d[98]
  PIN d[99]
    DIRECTION INPUT ;
    USE SIGNAL ;
    PORT
      LAYER M5 ;
        RECT  60.528 0 60.552 0.084 ;
    END
  END d[99]
  PIN d[9]
    DIRECTION INPUT ;
    USE SIGNAL ;
    PORT
      LAYER M5 ;
        RECT  2.88 0 2.904 0.084 ;
    END
  END d[9]
  PIN q[0]
    DIRECTION OUTPUT ;
    USE SIGNAL ;
    PORT
      LAYER M5 ;
        RECT  0.96 8.556 0.984 8.64 ;
    END
  END q[0]
  PIN q[100]
    DIRECTION OUTPUT ;
    USE SIGNAL ;
    PORT
      LAYER M5 ;
        RECT  65.04 8.556 65.064 8.64 ;
    END
  END q[100]
  PIN q[101]
    DIRECTION OUTPUT ;
    USE SIGNAL ;
    PORT
      LAYER M5 ;
        RECT  65.712 8.556 65.736 8.64 ;
    END
  END q[101]
  PIN q[102]
    DIRECTION OUTPUT ;
    USE SIGNAL ;
    PORT
      LAYER M5 ;
        RECT  66.336 8.556 66.36 8.64 ;
    END
  END q[102]
  PIN q[103]
    DIRECTION OUTPUT ;
    USE SIGNAL ;
    PORT
      LAYER M5 ;
        RECT  66.96 8.556 66.984 8.64 ;
    END
  END q[103]
  PIN q[104]
    DIRECTION OUTPUT ;
    USE SIGNAL ;
    PORT
      LAYER M5 ;
        RECT  67.632 8.556 67.656 8.64 ;
    END
  END q[104]
  PIN q[105]
    DIRECTION OUTPUT ;
    USE SIGNAL ;
    PORT
      LAYER M5 ;
        RECT  68.256 8.556 68.28 8.64 ;
    END
  END q[105]
  PIN q[106]
    DIRECTION OUTPUT ;
    USE SIGNAL ;
    PORT
      LAYER M5 ;
        RECT  68.88 8.556 68.904 8.64 ;
    END
  END q[106]
  PIN q[107]
    DIRECTION OUTPUT ;
    USE SIGNAL ;
    PORT
      LAYER M5 ;
        RECT  69.552 8.556 69.576 8.64 ;
    END
  END q[107]
  PIN q[108]
    DIRECTION OUTPUT ;
    USE SIGNAL ;
    PORT
      LAYER M5 ;
        RECT  70.176 8.556 70.2 8.64 ;
    END
  END q[108]
  PIN q[109]
    DIRECTION OUTPUT ;
    USE SIGNAL ;
    PORT
      LAYER M5 ;
        RECT  70.8 8.556 70.824 8.64 ;
    END
  END q[109]
  PIN q[10]
    DIRECTION OUTPUT ;
    USE SIGNAL ;
    PORT
      LAYER M5 ;
        RECT  7.392 8.556 7.416 8.64 ;
    END
  END q[10]
  PIN q[110]
    DIRECTION OUTPUT ;
    USE SIGNAL ;
    PORT
      LAYER M5 ;
        RECT  71.472 8.556 71.496 8.64 ;
    END
  END q[110]
  PIN q[111]
    DIRECTION OUTPUT ;
    USE SIGNAL ;
    PORT
      LAYER M5 ;
        RECT  72.096 8.556 72.12 8.64 ;
    END
  END q[111]
  PIN q[112]
    DIRECTION OUTPUT ;
    USE SIGNAL ;
    PORT
      LAYER M5 ;
        RECT  72.72 8.556 72.744 8.64 ;
    END
  END q[112]
  PIN q[113]
    DIRECTION OUTPUT ;
    USE SIGNAL ;
    PORT
      LAYER M5 ;
        RECT  73.392 8.556 73.416 8.64 ;
    END
  END q[113]
  PIN q[114]
    DIRECTION OUTPUT ;
    USE SIGNAL ;
    PORT
      LAYER M5 ;
        RECT  74.016 8.556 74.04 8.64 ;
    END
  END q[114]
  PIN q[115]
    DIRECTION OUTPUT ;
    USE SIGNAL ;
    PORT
      LAYER M5 ;
        RECT  74.64 8.556 74.664 8.64 ;
    END
  END q[115]
  PIN q[116]
    DIRECTION OUTPUT ;
    USE SIGNAL ;
    PORT
      LAYER M5 ;
        RECT  75.312 8.556 75.336 8.64 ;
    END
  END q[116]
  PIN q[117]
    DIRECTION OUTPUT ;
    USE SIGNAL ;
    PORT
      LAYER M5 ;
        RECT  75.936 8.556 75.96 8.64 ;
    END
  END q[117]
  PIN q[118]
    DIRECTION OUTPUT ;
    USE SIGNAL ;
    PORT
      LAYER M5 ;
        RECT  76.56 8.556 76.584 8.64 ;
    END
  END q[118]
  PIN q[119]
    DIRECTION OUTPUT ;
    USE SIGNAL ;
    PORT
      LAYER M5 ;
        RECT  77.232 8.556 77.256 8.64 ;
    END
  END q[119]
  PIN q[11]
    DIRECTION OUTPUT ;
    USE SIGNAL ;
    PORT
      LAYER M5 ;
        RECT  8.016 8.556 8.04 8.64 ;
    END
  END q[11]
  PIN q[120]
    DIRECTION OUTPUT ;
    USE SIGNAL ;
    PORT
      LAYER M5 ;
        RECT  77.856 8.556 77.88 8.64 ;
    END
  END q[120]
  PIN q[121]
    DIRECTION OUTPUT ;
    USE SIGNAL ;
    PORT
      LAYER M5 ;
        RECT  78.48 8.556 78.504 8.64 ;
    END
  END q[121]
  PIN q[122]
    DIRECTION OUTPUT ;
    USE SIGNAL ;
    PORT
      LAYER M5 ;
        RECT  79.152 8.556 79.176 8.64 ;
    END
  END q[122]
  PIN q[123]
    DIRECTION OUTPUT ;
    USE SIGNAL ;
    PORT
      LAYER M5 ;
        RECT  79.776 8.556 79.8 8.64 ;
    END
  END q[123]
  PIN q[124]
    DIRECTION OUTPUT ;
    USE SIGNAL ;
    PORT
      LAYER M5 ;
        RECT  80.4 8.556 80.424 8.64 ;
    END
  END q[124]
  PIN q[125]
    DIRECTION OUTPUT ;
    USE SIGNAL ;
    PORT
      LAYER M5 ;
        RECT  81.072 8.556 81.096 8.64 ;
    END
  END q[125]
  PIN q[126]
    DIRECTION OUTPUT ;
    USE SIGNAL ;
    PORT
      LAYER M5 ;
        RECT  81.696 8.556 81.72 8.64 ;
    END
  END q[126]
  PIN q[127]
    DIRECTION OUTPUT ;
    USE SIGNAL ;
    PORT
      LAYER M5 ;
        RECT  82.32 8.556 82.344 8.64 ;
    END
  END q[127]
  PIN q[128]
    DIRECTION OUTPUT ;
    USE SIGNAL ;
    PORT
      LAYER M5 ;
        RECT  82.992 8.556 83.016 8.64 ;
    END
  END q[128]
  PIN q[129]
    DIRECTION OUTPUT ;
    USE SIGNAL ;
    PORT
      LAYER M5 ;
        RECT  83.616 8.556 83.64 8.64 ;
    END
  END q[129]
  PIN q[12]
    DIRECTION OUTPUT ;
    USE SIGNAL ;
    PORT
      LAYER M5 ;
        RECT  8.64 8.556 8.664 8.64 ;
    END
  END q[12]
  PIN q[130]
    DIRECTION OUTPUT ;
    USE SIGNAL ;
    PORT
      LAYER M5 ;
        RECT  84.24 8.556 84.264 8.64 ;
    END
  END q[130]
  PIN q[131]
    DIRECTION OUTPUT ;
    USE SIGNAL ;
    PORT
      LAYER M5 ;
        RECT  84.912 8.556 84.936 8.64 ;
    END
  END q[131]
  PIN q[132]
    DIRECTION OUTPUT ;
    USE SIGNAL ;
    PORT
      LAYER M5 ;
        RECT  85.536 8.556 85.56 8.64 ;
    END
  END q[132]
  PIN q[133]
    DIRECTION OUTPUT ;
    USE SIGNAL ;
    PORT
      LAYER M5 ;
        RECT  86.16 8.556 86.184 8.64 ;
    END
  END q[133]
  PIN q[134]
    DIRECTION OUTPUT ;
    USE SIGNAL ;
    PORT
      LAYER M5 ;
        RECT  86.832 8.556 86.856 8.64 ;
    END
  END q[134]
  PIN q[135]
    DIRECTION OUTPUT ;
    USE SIGNAL ;
    PORT
      LAYER M5 ;
        RECT  87.456 8.556 87.48 8.64 ;
    END
  END q[135]
  PIN q[136]
    DIRECTION OUTPUT ;
    USE SIGNAL ;
    PORT
      LAYER M5 ;
        RECT  88.08 8.556 88.104 8.64 ;
    END
  END q[136]
  PIN q[137]
    DIRECTION OUTPUT ;
    USE SIGNAL ;
    PORT
      LAYER M5 ;
        RECT  88.752 8.556 88.776 8.64 ;
    END
  END q[137]
  PIN q[138]
    DIRECTION OUTPUT ;
    USE SIGNAL ;
    PORT
      LAYER M5 ;
        RECT  89.376 8.556 89.4 8.64 ;
    END
  END q[138]
  PIN q[139]
    DIRECTION OUTPUT ;
    USE SIGNAL ;
    PORT
      LAYER M5 ;
        RECT  90 8.556 90.024 8.64 ;
    END
  END q[139]
  PIN q[13]
    DIRECTION OUTPUT ;
    USE SIGNAL ;
    PORT
      LAYER M5 ;
        RECT  9.312 8.556 9.336 8.64 ;
    END
  END q[13]
  PIN q[140]
    DIRECTION OUTPUT ;
    USE SIGNAL ;
    PORT
      LAYER M5 ;
        RECT  90.672 8.556 90.696 8.64 ;
    END
  END q[140]
  PIN q[141]
    DIRECTION OUTPUT ;
    USE SIGNAL ;
    PORT
      LAYER M5 ;
        RECT  91.296 8.556 91.32 8.64 ;
    END
  END q[141]
  PIN q[142]
    DIRECTION OUTPUT ;
    USE SIGNAL ;
    PORT
      LAYER M5 ;
        RECT  91.92 8.556 91.944 8.64 ;
    END
  END q[142]
  PIN q[143]
    DIRECTION OUTPUT ;
    USE SIGNAL ;
    PORT
      LAYER M5 ;
        RECT  92.592 8.556 92.616 8.64 ;
    END
  END q[143]
  PIN q[144]
    DIRECTION OUTPUT ;
    USE SIGNAL ;
    PORT
      LAYER M5 ;
        RECT  93.216 8.556 93.24 8.64 ;
    END
  END q[144]
  PIN q[145]
    DIRECTION OUTPUT ;
    USE SIGNAL ;
    PORT
      LAYER M5 ;
        RECT  93.84 8.556 93.864 8.64 ;
    END
  END q[145]
  PIN q[146]
    DIRECTION OUTPUT ;
    USE SIGNAL ;
    PORT
      LAYER M5 ;
        RECT  94.512 8.556 94.536 8.64 ;
    END
  END q[146]
  PIN q[147]
    DIRECTION OUTPUT ;
    USE SIGNAL ;
    PORT
      LAYER M5 ;
        RECT  95.136 8.556 95.16 8.64 ;
    END
  END q[147]
  PIN q[148]
    DIRECTION OUTPUT ;
    USE SIGNAL ;
    PORT
      LAYER M5 ;
        RECT  95.808 8.556 95.832 8.64 ;
    END
  END q[148]
  PIN q[149]
    DIRECTION OUTPUT ;
    USE SIGNAL ;
    PORT
      LAYER M5 ;
        RECT  96.432 8.556 96.456 8.64 ;
    END
  END q[149]
  PIN q[14]
    DIRECTION OUTPUT ;
    USE SIGNAL ;
    PORT
      LAYER M5 ;
        RECT  9.936 8.556 9.96 8.64 ;
    END
  END q[14]
  PIN q[150]
    DIRECTION OUTPUT ;
    USE SIGNAL ;
    PORT
      LAYER M5 ;
        RECT  97.056 8.556 97.08 8.64 ;
    END
  END q[150]
  PIN q[151]
    DIRECTION OUTPUT ;
    USE SIGNAL ;
    PORT
      LAYER M5 ;
        RECT  97.728 8.556 97.752 8.64 ;
    END
  END q[151]
  PIN q[152]
    DIRECTION OUTPUT ;
    USE SIGNAL ;
    PORT
      LAYER M5 ;
        RECT  98.352 8.556 98.376 8.64 ;
    END
  END q[152]
  PIN q[153]
    DIRECTION OUTPUT ;
    USE SIGNAL ;
    PORT
      LAYER M5 ;
        RECT  98.976 8.556 99 8.64 ;
    END
  END q[153]
  PIN q[154]
    DIRECTION OUTPUT ;
    USE SIGNAL ;
    PORT
      LAYER M5 ;
        RECT  99.648 8.556 99.672 8.64 ;
    END
  END q[154]
  PIN q[155]
    DIRECTION OUTPUT ;
    USE SIGNAL ;
    PORT
      LAYER M5 ;
        RECT  100.272 8.556 100.296 8.64 ;
    END
  END q[155]
  PIN q[156]
    DIRECTION OUTPUT ;
    USE SIGNAL ;
    PORT
      LAYER M5 ;
        RECT  100.896 8.556 100.92 8.64 ;
    END
  END q[156]
  PIN q[157]
    DIRECTION OUTPUT ;
    USE SIGNAL ;
    PORT
      LAYER M5 ;
        RECT  101.568 8.556 101.592 8.64 ;
    END
  END q[157]
  PIN q[158]
    DIRECTION OUTPUT ;
    USE SIGNAL ;
    PORT
      LAYER M5 ;
        RECT  102.192 8.556 102.216 8.64 ;
    END
  END q[158]
  PIN q[159]
    DIRECTION OUTPUT ;
    USE SIGNAL ;
    PORT
      LAYER M5 ;
        RECT  102.816 8.556 102.84 8.64 ;
    END
  END q[159]
  PIN q[15]
    DIRECTION OUTPUT ;
    USE SIGNAL ;
    PORT
      LAYER M5 ;
        RECT  10.56 8.556 10.584 8.64 ;
    END
  END q[15]
  PIN q[160]
    DIRECTION OUTPUT ;
    USE SIGNAL ;
    PORT
      LAYER M5 ;
        RECT  103.44 8.556 103.464 8.64 ;
    END
  END q[160]
  PIN q[161]
    DIRECTION OUTPUT ;
    USE SIGNAL ;
    PORT
      LAYER M5 ;
        RECT  104.112 8.556 104.136 8.64 ;
    END
  END q[161]
  PIN q[162]
    DIRECTION OUTPUT ;
    USE SIGNAL ;
    PORT
      LAYER M5 ;
        RECT  104.736 8.556 104.76 8.64 ;
    END
  END q[162]
  PIN q[163]
    DIRECTION OUTPUT ;
    USE SIGNAL ;
    PORT
      LAYER M5 ;
        RECT  105.36 8.556 105.384 8.64 ;
    END
  END q[163]
  PIN q[164]
    DIRECTION OUTPUT ;
    USE SIGNAL ;
    PORT
      LAYER M5 ;
        RECT  106.032 8.556 106.056 8.64 ;
    END
  END q[164]
  PIN q[165]
    DIRECTION OUTPUT ;
    USE SIGNAL ;
    PORT
      LAYER M5 ;
        RECT  106.656 8.556 106.68 8.64 ;
    END
  END q[165]
  PIN q[166]
    DIRECTION OUTPUT ;
    USE SIGNAL ;
    PORT
      LAYER M5 ;
        RECT  107.28 8.556 107.304 8.64 ;
    END
  END q[166]
  PIN q[167]
    DIRECTION OUTPUT ;
    USE SIGNAL ;
    PORT
      LAYER M5 ;
        RECT  107.952 8.556 107.976 8.64 ;
    END
  END q[167]
  PIN q[168]
    DIRECTION OUTPUT ;
    USE SIGNAL ;
    PORT
      LAYER M5 ;
        RECT  108.576 8.556 108.6 8.64 ;
    END
  END q[168]
  PIN q[169]
    DIRECTION OUTPUT ;
    USE SIGNAL ;
    PORT
      LAYER M5 ;
        RECT  109.2 8.556 109.224 8.64 ;
    END
  END q[169]
  PIN q[16]
    DIRECTION OUTPUT ;
    USE SIGNAL ;
    PORT
      LAYER M5 ;
        RECT  11.232 8.556 11.256 8.64 ;
    END
  END q[16]
  PIN q[170]
    DIRECTION OUTPUT ;
    USE SIGNAL ;
    PORT
      LAYER M5 ;
        RECT  109.872 8.556 109.896 8.64 ;
    END
  END q[170]
  PIN q[171]
    DIRECTION OUTPUT ;
    USE SIGNAL ;
    PORT
      LAYER M5 ;
        RECT  110.496 8.556 110.52 8.64 ;
    END
  END q[171]
  PIN q[172]
    DIRECTION OUTPUT ;
    USE SIGNAL ;
    PORT
      LAYER M5 ;
        RECT  111.12 8.556 111.144 8.64 ;
    END
  END q[172]
  PIN q[173]
    DIRECTION OUTPUT ;
    USE SIGNAL ;
    PORT
      LAYER M5 ;
        RECT  111.792 8.556 111.816 8.64 ;
    END
  END q[173]
  PIN q[174]
    DIRECTION OUTPUT ;
    USE SIGNAL ;
    PORT
      LAYER M5 ;
        RECT  112.416 8.556 112.44 8.64 ;
    END
  END q[174]
  PIN q[175]
    DIRECTION OUTPUT ;
    USE SIGNAL ;
    PORT
      LAYER M5 ;
        RECT  113.04 8.556 113.064 8.64 ;
    END
  END q[175]
  PIN q[176]
    DIRECTION OUTPUT ;
    USE SIGNAL ;
    PORT
      LAYER M5 ;
        RECT  113.712 8.556 113.736 8.64 ;
    END
  END q[176]
  PIN q[177]
    DIRECTION OUTPUT ;
    USE SIGNAL ;
    PORT
      LAYER M5 ;
        RECT  114.336 8.556 114.36 8.64 ;
    END
  END q[177]
  PIN q[178]
    DIRECTION OUTPUT ;
    USE SIGNAL ;
    PORT
      LAYER M5 ;
        RECT  114.96 8.556 114.984 8.64 ;
    END
  END q[178]
  PIN q[179]
    DIRECTION OUTPUT ;
    USE SIGNAL ;
    PORT
      LAYER M5 ;
        RECT  115.632 8.556 115.656 8.64 ;
    END
  END q[179]
  PIN q[17]
    DIRECTION OUTPUT ;
    USE SIGNAL ;
    PORT
      LAYER M5 ;
        RECT  11.856 8.556 11.88 8.64 ;
    END
  END q[17]
  PIN q[180]
    DIRECTION OUTPUT ;
    USE SIGNAL ;
    PORT
      LAYER M5 ;
        RECT  116.256 8.556 116.28 8.64 ;
    END
  END q[180]
  PIN q[181]
    DIRECTION OUTPUT ;
    USE SIGNAL ;
    PORT
      LAYER M5 ;
        RECT  116.88 8.556 116.904 8.64 ;
    END
  END q[181]
  PIN q[182]
    DIRECTION OUTPUT ;
    USE SIGNAL ;
    PORT
      LAYER M5 ;
        RECT  117.552 8.556 117.576 8.64 ;
    END
  END q[182]
  PIN q[183]
    DIRECTION OUTPUT ;
    USE SIGNAL ;
    PORT
      LAYER M5 ;
        RECT  118.176 8.556 118.2 8.64 ;
    END
  END q[183]
  PIN q[184]
    DIRECTION OUTPUT ;
    USE SIGNAL ;
    PORT
      LAYER M5 ;
        RECT  118.8 8.556 118.824 8.64 ;
    END
  END q[184]
  PIN q[185]
    DIRECTION OUTPUT ;
    USE SIGNAL ;
    PORT
      LAYER M5 ;
        RECT  119.472 8.556 119.496 8.64 ;
    END
  END q[185]
  PIN q[186]
    DIRECTION OUTPUT ;
    USE SIGNAL ;
    PORT
      LAYER M5 ;
        RECT  120.096 8.556 120.12 8.64 ;
    END
  END q[186]
  PIN q[187]
    DIRECTION OUTPUT ;
    USE SIGNAL ;
    PORT
      LAYER M5 ;
        RECT  120.72 8.556 120.744 8.64 ;
    END
  END q[187]
  PIN q[188]
    DIRECTION OUTPUT ;
    USE SIGNAL ;
    PORT
      LAYER M5 ;
        RECT  121.392 8.556 121.416 8.64 ;
    END
  END q[188]
  PIN q[189]
    DIRECTION OUTPUT ;
    USE SIGNAL ;
    PORT
      LAYER M5 ;
        RECT  122.016 8.556 122.04 8.64 ;
    END
  END q[189]
  PIN q[18]
    DIRECTION OUTPUT ;
    USE SIGNAL ;
    PORT
      LAYER M5 ;
        RECT  12.528 8.556 12.552 8.64 ;
    END
  END q[18]
  PIN q[190]
    DIRECTION OUTPUT ;
    USE SIGNAL ;
    PORT
      LAYER M5 ;
        RECT  122.64 8.556 122.664 8.64 ;
    END
  END q[190]
  PIN q[191]
    DIRECTION OUTPUT ;
    USE SIGNAL ;
    PORT
      LAYER M5 ;
        RECT  123.36 8.556 123.384 8.64 ;
    END
  END q[191]
  PIN q[192]
    DIRECTION OUTPUT ;
    USE SIGNAL ;
    PORT
      LAYER M5 ;
        RECT  123.984 8.556 124.008 8.64 ;
    END
  END q[192]
  PIN q[193]
    DIRECTION OUTPUT ;
    USE SIGNAL ;
    PORT
      LAYER M5 ;
        RECT  124.608 8.556 124.632 8.64 ;
    END
  END q[193]
  PIN q[194]
    DIRECTION OUTPUT ;
    USE SIGNAL ;
    PORT
      LAYER M5 ;
        RECT  125.232 8.556 125.256 8.64 ;
    END
  END q[194]
  PIN q[195]
    DIRECTION OUTPUT ;
    USE SIGNAL ;
    PORT
      LAYER M5 ;
        RECT  125.904 8.556 125.928 8.64 ;
    END
  END q[195]
  PIN q[196]
    DIRECTION OUTPUT ;
    USE SIGNAL ;
    PORT
      LAYER M5 ;
        RECT  126.528 8.556 126.552 8.64 ;
    END
  END q[196]
  PIN q[197]
    DIRECTION OUTPUT ;
    USE SIGNAL ;
    PORT
      LAYER M5 ;
        RECT  127.152 8.556 127.176 8.64 ;
    END
  END q[197]
  PIN q[198]
    DIRECTION OUTPUT ;
    USE SIGNAL ;
    PORT
      LAYER M5 ;
        RECT  127.824 8.556 127.848 8.64 ;
    END
  END q[198]
  PIN q[199]
    DIRECTION OUTPUT ;
    USE SIGNAL ;
    PORT
      LAYER M5 ;
        RECT  128.448 8.556 128.472 8.64 ;
    END
  END q[199]
  PIN q[19]
    DIRECTION OUTPUT ;
    USE SIGNAL ;
    PORT
      LAYER M5 ;
        RECT  13.152 8.556 13.176 8.64 ;
    END
  END q[19]
  PIN q[1]
    DIRECTION OUTPUT ;
    USE SIGNAL ;
    PORT
      LAYER M5 ;
        RECT  1.632 8.556 1.656 8.64 ;
    END
  END q[1]
  PIN q[200]
    DIRECTION OUTPUT ;
    USE SIGNAL ;
    PORT
      LAYER M5 ;
        RECT  129.12 8.556 129.144 8.64 ;
    END
  END q[200]
  PIN q[201]
    DIRECTION OUTPUT ;
    USE SIGNAL ;
    PORT
      LAYER M5 ;
        RECT  129.744 8.556 129.768 8.64 ;
    END
  END q[201]
  PIN q[202]
    DIRECTION OUTPUT ;
    USE SIGNAL ;
    PORT
      LAYER M5 ;
        RECT  130.368 8.556 130.392 8.64 ;
    END
  END q[202]
  PIN q[203]
    DIRECTION OUTPUT ;
    USE SIGNAL ;
    PORT
      LAYER M5 ;
        RECT  131.04 8.556 131.064 8.64 ;
    END
  END q[203]
  PIN q[204]
    DIRECTION OUTPUT ;
    USE SIGNAL ;
    PORT
      LAYER M5 ;
        RECT  131.664 8.556 131.688 8.64 ;
    END
  END q[204]
  PIN q[205]
    DIRECTION OUTPUT ;
    USE SIGNAL ;
    PORT
      LAYER M5 ;
        RECT  132.288 8.556 132.312 8.64 ;
    END
  END q[205]
  PIN q[206]
    DIRECTION OUTPUT ;
    USE SIGNAL ;
    PORT
      LAYER M5 ;
        RECT  132.96 8.556 132.984 8.64 ;
    END
  END q[206]
  PIN q[207]
    DIRECTION OUTPUT ;
    USE SIGNAL ;
    PORT
      LAYER M5 ;
        RECT  133.584 8.556 133.608 8.64 ;
    END
  END q[207]
  PIN q[208]
    DIRECTION OUTPUT ;
    USE SIGNAL ;
    PORT
      LAYER M5 ;
        RECT  134.208 8.556 134.232 8.64 ;
    END
  END q[208]
  PIN q[209]
    DIRECTION OUTPUT ;
    USE SIGNAL ;
    PORT
      LAYER M5 ;
        RECT  134.88 8.556 134.904 8.64 ;
    END
  END q[209]
  PIN q[20]
    DIRECTION OUTPUT ;
    USE SIGNAL ;
    PORT
      LAYER M5 ;
        RECT  13.776 8.556 13.8 8.64 ;
    END
  END q[20]
  PIN q[210]
    DIRECTION OUTPUT ;
    USE SIGNAL ;
    PORT
      LAYER M5 ;
        RECT  135.504 8.556 135.528 8.64 ;
    END
  END q[210]
  PIN q[211]
    DIRECTION OUTPUT ;
    USE SIGNAL ;
    PORT
      LAYER M5 ;
        RECT  136.128 8.556 136.152 8.64 ;
    END
  END q[211]
  PIN q[212]
    DIRECTION OUTPUT ;
    USE SIGNAL ;
    PORT
      LAYER M5 ;
        RECT  136.8 8.556 136.824 8.64 ;
    END
  END q[212]
  PIN q[213]
    DIRECTION OUTPUT ;
    USE SIGNAL ;
    PORT
      LAYER M5 ;
        RECT  137.424 8.556 137.448 8.64 ;
    END
  END q[213]
  PIN q[214]
    DIRECTION OUTPUT ;
    USE SIGNAL ;
    PORT
      LAYER M5 ;
        RECT  138.048 8.556 138.072 8.64 ;
    END
  END q[214]
  PIN q[215]
    DIRECTION OUTPUT ;
    USE SIGNAL ;
    PORT
      LAYER M5 ;
        RECT  138.72 8.556 138.744 8.64 ;
    END
  END q[215]
  PIN q[216]
    DIRECTION OUTPUT ;
    USE SIGNAL ;
    PORT
      LAYER M5 ;
        RECT  139.344 8.556 139.368 8.64 ;
    END
  END q[216]
  PIN q[217]
    DIRECTION OUTPUT ;
    USE SIGNAL ;
    PORT
      LAYER M5 ;
        RECT  139.968 8.556 139.992 8.64 ;
    END
  END q[217]
  PIN q[218]
    DIRECTION OUTPUT ;
    USE SIGNAL ;
    PORT
      LAYER M5 ;
        RECT  140.64 8.556 140.664 8.64 ;
    END
  END q[218]
  PIN q[219]
    DIRECTION OUTPUT ;
    USE SIGNAL ;
    PORT
      LAYER M5 ;
        RECT  141.264 8.556 141.288 8.64 ;
    END
  END q[219]
  PIN q[21]
    DIRECTION OUTPUT ;
    USE SIGNAL ;
    PORT
      LAYER M5 ;
        RECT  14.448 8.556 14.472 8.64 ;
    END
  END q[21]
  PIN q[220]
    DIRECTION OUTPUT ;
    USE SIGNAL ;
    PORT
      LAYER M5 ;
        RECT  141.888 8.556 141.912 8.64 ;
    END
  END q[220]
  PIN q[221]
    DIRECTION OUTPUT ;
    USE SIGNAL ;
    PORT
      LAYER M5 ;
        RECT  142.56 8.556 142.584 8.64 ;
    END
  END q[221]
  PIN q[222]
    DIRECTION OUTPUT ;
    USE SIGNAL ;
    PORT
      LAYER M5 ;
        RECT  143.184 8.556 143.208 8.64 ;
    END
  END q[222]
  PIN q[223]
    DIRECTION OUTPUT ;
    USE SIGNAL ;
    PORT
      LAYER M5 ;
        RECT  143.856 8.556 143.88 8.64 ;
    END
  END q[223]
  PIN q[224]
    DIRECTION OUTPUT ;
    USE SIGNAL ;
    PORT
      LAYER M5 ;
        RECT  144.48 8.556 144.504 8.64 ;
    END
  END q[224]
  PIN q[225]
    DIRECTION OUTPUT ;
    USE SIGNAL ;
    PORT
      LAYER M5 ;
        RECT  145.104 8.556 145.128 8.64 ;
    END
  END q[225]
  PIN q[226]
    DIRECTION OUTPUT ;
    USE SIGNAL ;
    PORT
      LAYER M5 ;
        RECT  145.776 8.556 145.8 8.64 ;
    END
  END q[226]
  PIN q[227]
    DIRECTION OUTPUT ;
    USE SIGNAL ;
    PORT
      LAYER M5 ;
        RECT  146.4 8.556 146.424 8.64 ;
    END
  END q[227]
  PIN q[228]
    DIRECTION OUTPUT ;
    USE SIGNAL ;
    PORT
      LAYER M5 ;
        RECT  147.024 8.556 147.048 8.64 ;
    END
  END q[228]
  PIN q[229]
    DIRECTION OUTPUT ;
    USE SIGNAL ;
    PORT
      LAYER M5 ;
        RECT  147.696 8.556 147.72 8.64 ;
    END
  END q[229]
  PIN q[22]
    DIRECTION OUTPUT ;
    USE SIGNAL ;
    PORT
      LAYER M5 ;
        RECT  15.072 8.556 15.096 8.64 ;
    END
  END q[22]
  PIN q[230]
    DIRECTION OUTPUT ;
    USE SIGNAL ;
    PORT
      LAYER M5 ;
        RECT  148.32 8.556 148.344 8.64 ;
    END
  END q[230]
  PIN q[231]
    DIRECTION OUTPUT ;
    USE SIGNAL ;
    PORT
      LAYER M5 ;
        RECT  148.944 8.556 148.968 8.64 ;
    END
  END q[231]
  PIN q[232]
    DIRECTION OUTPUT ;
    USE SIGNAL ;
    PORT
      LAYER M5 ;
        RECT  149.616 8.556 149.64 8.64 ;
    END
  END q[232]
  PIN q[233]
    DIRECTION OUTPUT ;
    USE SIGNAL ;
    PORT
      LAYER M5 ;
        RECT  150.24 8.556 150.264 8.64 ;
    END
  END q[233]
  PIN q[234]
    DIRECTION OUTPUT ;
    USE SIGNAL ;
    PORT
      LAYER M5 ;
        RECT  150.864 8.556 150.888 8.64 ;
    END
  END q[234]
  PIN q[235]
    DIRECTION OUTPUT ;
    USE SIGNAL ;
    PORT
      LAYER M5 ;
        RECT  151.536 8.556 151.56 8.64 ;
    END
  END q[235]
  PIN q[236]
    DIRECTION OUTPUT ;
    USE SIGNAL ;
    PORT
      LAYER M5 ;
        RECT  152.16 8.556 152.184 8.64 ;
    END
  END q[236]
  PIN q[237]
    DIRECTION OUTPUT ;
    USE SIGNAL ;
    PORT
      LAYER M5 ;
        RECT  152.784 8.556 152.808 8.64 ;
    END
  END q[237]
  PIN q[238]
    DIRECTION OUTPUT ;
    USE SIGNAL ;
    PORT
      LAYER M5 ;
        RECT  153.456 8.556 153.48 8.64 ;
    END
  END q[238]
  PIN q[239]
    DIRECTION OUTPUT ;
    USE SIGNAL ;
    PORT
      LAYER M5 ;
        RECT  154.08 8.556 154.104 8.64 ;
    END
  END q[239]
  PIN q[23]
    DIRECTION OUTPUT ;
    USE SIGNAL ;
    PORT
      LAYER M5 ;
        RECT  15.696 8.556 15.72 8.64 ;
    END
  END q[23]
  PIN q[240]
    DIRECTION OUTPUT ;
    USE SIGNAL ;
    PORT
      LAYER M5 ;
        RECT  154.704 8.556 154.728 8.64 ;
    END
  END q[240]
  PIN q[241]
    DIRECTION OUTPUT ;
    USE SIGNAL ;
    PORT
      LAYER M5 ;
        RECT  155.376 8.556 155.4 8.64 ;
    END
  END q[241]
  PIN q[242]
    DIRECTION OUTPUT ;
    USE SIGNAL ;
    PORT
      LAYER M5 ;
        RECT  156 8.556 156.024 8.64 ;
    END
  END q[242]
  PIN q[243]
    DIRECTION OUTPUT ;
    USE SIGNAL ;
    PORT
      LAYER M5 ;
        RECT  156.624 8.556 156.648 8.64 ;
    END
  END q[243]
  PIN q[244]
    DIRECTION OUTPUT ;
    USE SIGNAL ;
    PORT
      LAYER M5 ;
        RECT  157.296 8.556 157.32 8.64 ;
    END
  END q[244]
  PIN q[245]
    DIRECTION OUTPUT ;
    USE SIGNAL ;
    PORT
      LAYER M5 ;
        RECT  157.92 8.556 157.944 8.64 ;
    END
  END q[245]
  PIN q[246]
    DIRECTION OUTPUT ;
    USE SIGNAL ;
    PORT
      LAYER M5 ;
        RECT  158.544 8.556 158.568 8.64 ;
    END
  END q[246]
  PIN q[247]
    DIRECTION OUTPUT ;
    USE SIGNAL ;
    PORT
      LAYER M5 ;
        RECT  159.216 8.556 159.24 8.64 ;
    END
  END q[247]
  PIN q[248]
    DIRECTION OUTPUT ;
    USE SIGNAL ;
    PORT
      LAYER M5 ;
        RECT  159.84 8.556 159.864 8.64 ;
    END
  END q[248]
  PIN q[249]
    DIRECTION OUTPUT ;
    USE SIGNAL ;
    PORT
      LAYER M5 ;
        RECT  160.464 8.556 160.488 8.64 ;
    END
  END q[249]
  PIN q[24]
    DIRECTION OUTPUT ;
    USE SIGNAL ;
    PORT
      LAYER M5 ;
        RECT  16.368 8.556 16.392 8.64 ;
    END
  END q[24]
  PIN q[250]
    DIRECTION OUTPUT ;
    USE SIGNAL ;
    PORT
      LAYER M5 ;
        RECT  161.136 8.556 161.16 8.64 ;
    END
  END q[250]
  PIN q[251]
    DIRECTION OUTPUT ;
    USE SIGNAL ;
    PORT
      LAYER M5 ;
        RECT  161.76 8.556 161.784 8.64 ;
    END
  END q[251]
  PIN q[252]
    DIRECTION OUTPUT ;
    USE SIGNAL ;
    PORT
      LAYER M5 ;
        RECT  162.384 8.556 162.408 8.64 ;
    END
  END q[252]
  PIN q[253]
    DIRECTION OUTPUT ;
    USE SIGNAL ;
    PORT
      LAYER M5 ;
        RECT  163.056 8.556 163.08 8.64 ;
    END
  END q[253]
  PIN q[254]
    DIRECTION OUTPUT ;
    USE SIGNAL ;
    PORT
      LAYER M5 ;
        RECT  163.68 8.556 163.704 8.64 ;
    END
  END q[254]
  PIN q[255]
    DIRECTION OUTPUT ;
    USE SIGNAL ;
    PORT
      LAYER M5 ;
        RECT  164.304 8.556 164.328 8.64 ;
    END
  END q[255]
  PIN q[25]
    DIRECTION OUTPUT ;
    USE SIGNAL ;
    PORT
      LAYER M5 ;
        RECT  16.992 8.556 17.016 8.64 ;
    END
  END q[25]
  PIN q[26]
    DIRECTION OUTPUT ;
    USE SIGNAL ;
    PORT
      LAYER M5 ;
        RECT  17.616 8.556 17.64 8.64 ;
    END
  END q[26]
  PIN q[27]
    DIRECTION OUTPUT ;
    USE SIGNAL ;
    PORT
      LAYER M5 ;
        RECT  18.288 8.556 18.312 8.64 ;
    END
  END q[27]
  PIN q[28]
    DIRECTION OUTPUT ;
    USE SIGNAL ;
    PORT
      LAYER M5 ;
        RECT  18.912 8.556 18.936 8.64 ;
    END
  END q[28]
  PIN q[29]
    DIRECTION OUTPUT ;
    USE SIGNAL ;
    PORT
      LAYER M5 ;
        RECT  19.536 8.556 19.56 8.64 ;
    END
  END q[29]
  PIN q[2]
    DIRECTION OUTPUT ;
    USE SIGNAL ;
    PORT
      LAYER M5 ;
        RECT  2.256 8.556 2.28 8.64 ;
    END
  END q[2]
  PIN q[30]
    DIRECTION OUTPUT ;
    USE SIGNAL ;
    PORT
      LAYER M5 ;
        RECT  20.208 8.556 20.232 8.64 ;
    END
  END q[30]
  PIN q[31]
    DIRECTION OUTPUT ;
    USE SIGNAL ;
    PORT
      LAYER M5 ;
        RECT  20.832 8.556 20.856 8.64 ;
    END
  END q[31]
  PIN q[32]
    DIRECTION OUTPUT ;
    USE SIGNAL ;
    PORT
      LAYER M5 ;
        RECT  21.456 8.556 21.48 8.64 ;
    END
  END q[32]
  PIN q[33]
    DIRECTION OUTPUT ;
    USE SIGNAL ;
    PORT
      LAYER M5 ;
        RECT  22.128 8.556 22.152 8.64 ;
    END
  END q[33]
  PIN q[34]
    DIRECTION OUTPUT ;
    USE SIGNAL ;
    PORT
      LAYER M5 ;
        RECT  22.752 8.556 22.776 8.64 ;
    END
  END q[34]
  PIN q[35]
    DIRECTION OUTPUT ;
    USE SIGNAL ;
    PORT
      LAYER M5 ;
        RECT  23.376 8.556 23.4 8.64 ;
    END
  END q[35]
  PIN q[36]
    DIRECTION OUTPUT ;
    USE SIGNAL ;
    PORT
      LAYER M5 ;
        RECT  24.048 8.556 24.072 8.64 ;
    END
  END q[36]
  PIN q[37]
    DIRECTION OUTPUT ;
    USE SIGNAL ;
    PORT
      LAYER M5 ;
        RECT  24.672 8.556 24.696 8.64 ;
    END
  END q[37]
  PIN q[38]
    DIRECTION OUTPUT ;
    USE SIGNAL ;
    PORT
      LAYER M5 ;
        RECT  25.296 8.556 25.32 8.64 ;
    END
  END q[38]
  PIN q[39]
    DIRECTION OUTPUT ;
    USE SIGNAL ;
    PORT
      LAYER M5 ;
        RECT  25.968 8.556 25.992 8.64 ;
    END
  END q[39]
  PIN q[3]
    DIRECTION OUTPUT ;
    USE SIGNAL ;
    PORT
      LAYER M5 ;
        RECT  2.88 8.556 2.904 8.64 ;
    END
  END q[3]
  PIN q[40]
    DIRECTION OUTPUT ;
    USE SIGNAL ;
    PORT
      LAYER M5 ;
        RECT  26.592 8.556 26.616 8.64 ;
    END
  END q[40]
  PIN q[41]
    DIRECTION OUTPUT ;
    USE SIGNAL ;
    PORT
      LAYER M5 ;
        RECT  27.216 8.556 27.24 8.64 ;
    END
  END q[41]
  PIN q[42]
    DIRECTION OUTPUT ;
    USE SIGNAL ;
    PORT
      LAYER M5 ;
        RECT  27.888 8.556 27.912 8.64 ;
    END
  END q[42]
  PIN q[43]
    DIRECTION OUTPUT ;
    USE SIGNAL ;
    PORT
      LAYER M5 ;
        RECT  28.512 8.556 28.536 8.64 ;
    END
  END q[43]
  PIN q[44]
    DIRECTION OUTPUT ;
    USE SIGNAL ;
    PORT
      LAYER M5 ;
        RECT  29.136 8.556 29.16 8.64 ;
    END
  END q[44]
  PIN q[45]
    DIRECTION OUTPUT ;
    USE SIGNAL ;
    PORT
      LAYER M5 ;
        RECT  29.808 8.556 29.832 8.64 ;
    END
  END q[45]
  PIN q[46]
    DIRECTION OUTPUT ;
    USE SIGNAL ;
    PORT
      LAYER M5 ;
        RECT  30.432 8.556 30.456 8.64 ;
    END
  END q[46]
  PIN q[47]
    DIRECTION OUTPUT ;
    USE SIGNAL ;
    PORT
      LAYER M5 ;
        RECT  31.056 8.556 31.08 8.64 ;
    END
  END q[47]
  PIN q[48]
    DIRECTION OUTPUT ;
    USE SIGNAL ;
    PORT
      LAYER M5 ;
        RECT  31.728 8.556 31.752 8.64 ;
    END
  END q[48]
  PIN q[49]
    DIRECTION OUTPUT ;
    USE SIGNAL ;
    PORT
      LAYER M5 ;
        RECT  32.352 8.556 32.376 8.64 ;
    END
  END q[49]
  PIN q[4]
    DIRECTION OUTPUT ;
    USE SIGNAL ;
    PORT
      LAYER M5 ;
        RECT  3.552 8.556 3.576 8.64 ;
    END
  END q[4]
  PIN q[50]
    DIRECTION OUTPUT ;
    USE SIGNAL ;
    PORT
      LAYER M5 ;
        RECT  32.976 8.556 33 8.64 ;
    END
  END q[50]
  PIN q[51]
    DIRECTION OUTPUT ;
    USE SIGNAL ;
    PORT
      LAYER M5 ;
        RECT  33.648 8.556 33.672 8.64 ;
    END
  END q[51]
  PIN q[52]
    DIRECTION OUTPUT ;
    USE SIGNAL ;
    PORT
      LAYER M5 ;
        RECT  34.272 8.556 34.296 8.64 ;
    END
  END q[52]
  PIN q[53]
    DIRECTION OUTPUT ;
    USE SIGNAL ;
    PORT
      LAYER M5 ;
        RECT  34.896 8.556 34.92 8.64 ;
    END
  END q[53]
  PIN q[54]
    DIRECTION OUTPUT ;
    USE SIGNAL ;
    PORT
      LAYER M5 ;
        RECT  35.568 8.556 35.592 8.64 ;
    END
  END q[54]
  PIN q[55]
    DIRECTION OUTPUT ;
    USE SIGNAL ;
    PORT
      LAYER M5 ;
        RECT  36.192 8.556 36.216 8.64 ;
    END
  END q[55]
  PIN q[56]
    DIRECTION OUTPUT ;
    USE SIGNAL ;
    PORT
      LAYER M5 ;
        RECT  36.816 8.556 36.84 8.64 ;
    END
  END q[56]
  PIN q[57]
    DIRECTION OUTPUT ;
    USE SIGNAL ;
    PORT
      LAYER M5 ;
        RECT  37.488 8.556 37.512 8.64 ;
    END
  END q[57]
  PIN q[58]
    DIRECTION OUTPUT ;
    USE SIGNAL ;
    PORT
      LAYER M5 ;
        RECT  38.112 8.556 38.136 8.64 ;
    END
  END q[58]
  PIN q[59]
    DIRECTION OUTPUT ;
    USE SIGNAL ;
    PORT
      LAYER M5 ;
        RECT  38.736 8.556 38.76 8.64 ;
    END
  END q[59]
  PIN q[5]
    DIRECTION OUTPUT ;
    USE SIGNAL ;
    PORT
      LAYER M5 ;
        RECT  4.176 8.556 4.2 8.64 ;
    END
  END q[5]
  PIN q[60]
    DIRECTION OUTPUT ;
    USE SIGNAL ;
    PORT
      LAYER M5 ;
        RECT  39.408 8.556 39.432 8.64 ;
    END
  END q[60]
  PIN q[61]
    DIRECTION OUTPUT ;
    USE SIGNAL ;
    PORT
      LAYER M5 ;
        RECT  40.032 8.556 40.056 8.64 ;
    END
  END q[61]
  PIN q[62]
    DIRECTION OUTPUT ;
    USE SIGNAL ;
    PORT
      LAYER M5 ;
        RECT  40.656 8.556 40.68 8.64 ;
    END
  END q[62]
  PIN q[63]
    DIRECTION OUTPUT ;
    USE SIGNAL ;
    PORT
      LAYER M5 ;
        RECT  41.328 8.556 41.352 8.64 ;
    END
  END q[63]
  PIN q[64]
    DIRECTION OUTPUT ;
    USE SIGNAL ;
    PORT
      LAYER M5 ;
        RECT  41.952 8.556 41.976 8.64 ;
    END
  END q[64]
  PIN q[65]
    DIRECTION OUTPUT ;
    USE SIGNAL ;
    PORT
      LAYER M5 ;
        RECT  42.624 8.556 42.648 8.64 ;
    END
  END q[65]
  PIN q[66]
    DIRECTION OUTPUT ;
    USE SIGNAL ;
    PORT
      LAYER M5 ;
        RECT  43.248 8.556 43.272 8.64 ;
    END
  END q[66]
  PIN q[67]
    DIRECTION OUTPUT ;
    USE SIGNAL ;
    PORT
      LAYER M5 ;
        RECT  43.872 8.556 43.896 8.64 ;
    END
  END q[67]
  PIN q[68]
    DIRECTION OUTPUT ;
    USE SIGNAL ;
    PORT
      LAYER M5 ;
        RECT  44.544 8.556 44.568 8.64 ;
    END
  END q[68]
  PIN q[69]
    DIRECTION OUTPUT ;
    USE SIGNAL ;
    PORT
      LAYER M5 ;
        RECT  45.168 8.556 45.192 8.64 ;
    END
  END q[69]
  PIN q[6]
    DIRECTION OUTPUT ;
    USE SIGNAL ;
    PORT
      LAYER M5 ;
        RECT  4.8 8.556 4.824 8.64 ;
    END
  END q[6]
  PIN q[70]
    DIRECTION OUTPUT ;
    USE SIGNAL ;
    PORT
      LAYER M5 ;
        RECT  45.84 8.556 45.864 8.64 ;
    END
  END q[70]
  PIN q[71]
    DIRECTION OUTPUT ;
    USE SIGNAL ;
    PORT
      LAYER M5 ;
        RECT  46.464 8.556 46.488 8.64 ;
    END
  END q[71]
  PIN q[72]
    DIRECTION OUTPUT ;
    USE SIGNAL ;
    PORT
      LAYER M5 ;
        RECT  47.088 8.556 47.112 8.64 ;
    END
  END q[72]
  PIN q[73]
    DIRECTION OUTPUT ;
    USE SIGNAL ;
    PORT
      LAYER M5 ;
        RECT  47.76 8.556 47.784 8.64 ;
    END
  END q[73]
  PIN q[74]
    DIRECTION OUTPUT ;
    USE SIGNAL ;
    PORT
      LAYER M5 ;
        RECT  48.384 8.556 48.408 8.64 ;
    END
  END q[74]
  PIN q[75]
    DIRECTION OUTPUT ;
    USE SIGNAL ;
    PORT
      LAYER M5 ;
        RECT  49.008 8.556 49.032 8.64 ;
    END
  END q[75]
  PIN q[76]
    DIRECTION OUTPUT ;
    USE SIGNAL ;
    PORT
      LAYER M5 ;
        RECT  49.68 8.556 49.704 8.64 ;
    END
  END q[76]
  PIN q[77]
    DIRECTION OUTPUT ;
    USE SIGNAL ;
    PORT
      LAYER M5 ;
        RECT  50.304 8.556 50.328 8.64 ;
    END
  END q[77]
  PIN q[78]
    DIRECTION OUTPUT ;
    USE SIGNAL ;
    PORT
      LAYER M5 ;
        RECT  50.928 8.556 50.952 8.64 ;
    END
  END q[78]
  PIN q[79]
    DIRECTION OUTPUT ;
    USE SIGNAL ;
    PORT
      LAYER M5 ;
        RECT  51.6 8.556 51.624 8.64 ;
    END
  END q[79]
  PIN q[7]
    DIRECTION OUTPUT ;
    USE SIGNAL ;
    PORT
      LAYER M5 ;
        RECT  5.472 8.556 5.496 8.64 ;
    END
  END q[7]
  PIN q[80]
    DIRECTION OUTPUT ;
    USE SIGNAL ;
    PORT
      LAYER M5 ;
        RECT  52.224 8.556 52.248 8.64 ;
    END
  END q[80]
  PIN q[81]
    DIRECTION OUTPUT ;
    USE SIGNAL ;
    PORT
      LAYER M5 ;
        RECT  52.848 8.556 52.872 8.64 ;
    END
  END q[81]
  PIN q[82]
    DIRECTION OUTPUT ;
    USE SIGNAL ;
    PORT
      LAYER M5 ;
        RECT  53.52 8.556 53.544 8.64 ;
    END
  END q[82]
  PIN q[83]
    DIRECTION OUTPUT ;
    USE SIGNAL ;
    PORT
      LAYER M5 ;
        RECT  54.144 8.556 54.168 8.64 ;
    END
  END q[83]
  PIN q[84]
    DIRECTION OUTPUT ;
    USE SIGNAL ;
    PORT
      LAYER M5 ;
        RECT  54.768 8.556 54.792 8.64 ;
    END
  END q[84]
  PIN q[85]
    DIRECTION OUTPUT ;
    USE SIGNAL ;
    PORT
      LAYER M5 ;
        RECT  55.44 8.556 55.464 8.64 ;
    END
  END q[85]
  PIN q[86]
    DIRECTION OUTPUT ;
    USE SIGNAL ;
    PORT
      LAYER M5 ;
        RECT  56.064 8.556 56.088 8.64 ;
    END
  END q[86]
  PIN q[87]
    DIRECTION OUTPUT ;
    USE SIGNAL ;
    PORT
      LAYER M5 ;
        RECT  56.688 8.556 56.712 8.64 ;
    END
  END q[87]
  PIN q[88]
    DIRECTION OUTPUT ;
    USE SIGNAL ;
    PORT
      LAYER M5 ;
        RECT  57.36 8.556 57.384 8.64 ;
    END
  END q[88]
  PIN q[89]
    DIRECTION OUTPUT ;
    USE SIGNAL ;
    PORT
      LAYER M5 ;
        RECT  57.984 8.556 58.008 8.64 ;
    END
  END q[89]
  PIN q[8]
    DIRECTION OUTPUT ;
    USE SIGNAL ;
    PORT
      LAYER M5 ;
        RECT  6.096 8.556 6.12 8.64 ;
    END
  END q[8]
  PIN q[90]
    DIRECTION OUTPUT ;
    USE SIGNAL ;
    PORT
      LAYER M5 ;
        RECT  58.608 8.556 58.632 8.64 ;
    END
  END q[90]
  PIN q[91]
    DIRECTION OUTPUT ;
    USE SIGNAL ;
    PORT
      LAYER M5 ;
        RECT  59.28 8.556 59.304 8.64 ;
    END
  END q[91]
  PIN q[92]
    DIRECTION OUTPUT ;
    USE SIGNAL ;
    PORT
      LAYER M5 ;
        RECT  59.904 8.556 59.928 8.64 ;
    END
  END q[92]
  PIN q[93]
    DIRECTION OUTPUT ;
    USE SIGNAL ;
    PORT
      LAYER M5 ;
        RECT  60.528 8.556 60.552 8.64 ;
    END
  END q[93]
  PIN q[94]
    DIRECTION OUTPUT ;
    USE SIGNAL ;
    PORT
      LAYER M5 ;
        RECT  61.2 8.556 61.224 8.64 ;
    END
  END q[94]
  PIN q[95]
    DIRECTION OUTPUT ;
    USE SIGNAL ;
    PORT
      LAYER M5 ;
        RECT  61.824 8.556 61.848 8.64 ;
    END
  END q[95]
  PIN q[96]
    DIRECTION OUTPUT ;
    USE SIGNAL ;
    PORT
      LAYER M5 ;
        RECT  62.496 8.556 62.52 8.64 ;
    END
  END q[96]
  PIN q[97]
    DIRECTION OUTPUT ;
    USE SIGNAL ;
    PORT
      LAYER M5 ;
        RECT  63.12 8.556 63.144 8.64 ;
    END
  END q[97]
  PIN q[98]
    DIRECTION OUTPUT ;
    USE SIGNAL ;
    PORT
      LAYER M5 ;
        RECT  63.792 8.556 63.816 8.64 ;
    END
  END q[98]
  PIN q[99]
    DIRECTION OUTPUT ;
    USE SIGNAL ;
    PORT
      LAYER M5 ;
        RECT  64.416 8.556 64.44 8.64 ;
    END
  END q[99]
  PIN q[9]
    DIRECTION OUTPUT ;
    USE SIGNAL ;
    PORT
      LAYER M5 ;
        RECT  6.72 8.556 6.744 8.64 ;
    END
  END q[9]
  PIN rst_n
    DIRECTION INPUT ;
    USE SIGNAL ;
    PORT
      LAYER M4 ;
        RECT  0 4.608 0.084 4.632 ;
    END
  END rst_n
  PIN VDD
    DIRECTION INOUT ;
    USE POWER ;
    PORT
      LAYER M5 ;
        RECT  159.192 2.151 159.312 6.489 ;
        RECT  153.792 2.151 153.912 6.489 ;
        RECT  148.392 2.151 148.512 6.489 ;
        RECT  142.992 2.151 143.112 6.489 ;
        RECT  137.592 2.151 137.712 6.489 ;
        RECT  132.192 2.151 132.312 6.489 ;
        RECT  126.792 2.151 126.912 6.489 ;
        RECT  121.392 2.151 121.512 6.489 ;
        RECT  115.992 2.151 116.112 6.489 ;
        RECT  110.592 2.151 110.712 6.489 ;
        RECT  105.192 2.151 105.312 6.489 ;
        RECT  99.792 2.151 99.912 6.489 ;
        RECT  94.392 2.151 94.512 6.489 ;
        RECT  88.992 2.151 89.112 6.489 ;
        RECT  83.592 2.151 83.712 6.489 ;
        RECT  78.192 2.151 78.312 6.489 ;
        RECT  72.792 2.151 72.912 6.489 ;
        RECT  67.392 2.151 67.512 6.489 ;
        RECT  61.992 2.151 62.112 6.489 ;
        RECT  56.592 2.151 56.712 6.489 ;
        RECT  51.192 2.151 51.312 6.489 ;
        RECT  45.792 2.151 45.912 6.489 ;
        RECT  40.392 2.151 40.512 6.489 ;
        RECT  34.992 2.151 35.112 6.489 ;
        RECT  29.592 2.151 29.712 6.489 ;
        RECT  24.192 2.151 24.312 6.489 ;
        RECT  18.792 2.151 18.912 6.489 ;
        RECT  13.392 2.151 13.512 6.489 ;
        RECT  7.992 2.151 8.112 6.489 ;
        RECT  2.592 2.151 2.712 6.489 ;
    END
  END VDD
  PIN VSS
    DIRECTION INOUT ;
    USE GROUND ;
    PORT
      LAYER M5 ;
        RECT  159 2.137 159.12 6.503 ;
        RECT  153.6 2.137 153.72 6.503 ;
        RECT  148.2 2.137 148.32 6.503 ;
        RECT  142.8 2.137 142.92 6.503 ;
        RECT  137.4 2.137 137.52 6.503 ;
        RECT  132 2.137 132.12 6.503 ;
        RECT  126.6 2.137 126.72 6.503 ;
        RECT  121.2 2.137 121.32 6.503 ;
        RECT  115.8 2.137 115.92 6.503 ;
        RECT  110.4 2.137 110.52 6.503 ;
        RECT  105 2.137 105.12 6.503 ;
        RECT  99.6 2.137 99.72 6.503 ;
        RECT  94.2 2.137 94.32 6.503 ;
        RECT  88.8 2.137 88.92 6.503 ;
        RECT  83.4 2.137 83.52 6.503 ;
        RECT  78 2.137 78.12 6.503 ;
        RECT  72.6 2.137 72.72 6.503 ;
        RECT  67.2 2.137 67.32 6.503 ;
        RECT  61.8 2.137 61.92 6.503 ;
        RECT  56.4 2.137 56.52 6.503 ;
        RECT  51 2.137 51.12 6.503 ;
        RECT  45.6 2.137 45.72 6.503 ;
        RECT  40.2 2.137 40.32 6.503 ;
        RECT  34.8 2.137 34.92 6.503 ;
        RECT  29.4 2.137 29.52 6.503 ;
        RECT  24 2.137 24.12 6.503 ;
        RECT  18.6 2.137 18.72 6.503 ;
        RECT  13.2 2.137 13.32 6.503 ;
        RECT  7.8 2.137 7.92 6.503 ;
        RECT  2.4 2.137 2.52 6.503 ;
    END
  END VSS
  # OT_OBS_CLOSED layer=M5 d_um=1.536 added=119
  OBS
    LAYER RVTN ;
     RECT  2.16 2.16 163.728 2.295 ;
     RECT  2.16 2.565 163.728 2.835 ;
     RECT  2.16 3.105 163.728 3.375 ;
     RECT  2.16 3.645 163.728 3.915 ;
     RECT  2.16 4.185 163.728 4.455 ;
     RECT  2.16 4.725 163.728 4.995 ;
     RECT  2.16 5.265 163.728 5.535 ;
     RECT  2.16 5.805 163.728 6.075 ;
     RECT  2.16 6.345 163.728 6.48 ;
    LAYER RVTP ;
     RECT  2.16 2.295 163.728 2.565 ;
     RECT  2.16 2.835 163.728 3.105 ;
     RECT  2.16 3.375 163.728 3.645 ;
     RECT  2.16 3.915 163.728 4.185 ;
     RECT  2.16 4.455 163.728 4.725 ;
     RECT  2.16 4.995 163.728 5.265 ;
     RECT  2.16 5.535 163.728 5.805 ;
     RECT  2.16 6.075 163.728 6.345 ;
    LAYER M1 ;
     RECT  2.16 2.151 163.728 6.489 ;
    LAYER M2 ;
     RECT  2.16 2.151 3.343 6.489 ;
     RECT  3.343 2.106 5.243 6.489 ;
     RECT  5.243 2.151 23.359 6.489 ;
     RECT  23.359 2.151 23.459 6.84 ;
     RECT  23.459 2.151 163.728 6.489 ;
     RECT  163.728 4.968 164.363 4.986 ;
    LAYER M3 ;
     RECT  2.304 0.091 2.322 0.139 ;
     RECT  147.636 0.091 147.654 0.523 ;
     RECT  91.224 0.571 91.242 0.619 ;
     RECT  4.356 0.091 4.374 1.723 ;
     RECT  7.992 0.571 8.658 1.723 ;
     RECT  13.104 0.571 13.734 1.723 ;
     RECT  18.252 0.571 19.458 1.723 ;
     RECT  23.976 0.571 24.534 1.723 ;
     RECT  29.088 0.571 29.718 1.723 ;
     RECT  30.888 0.571 30.906 1.723 ;
     RECT  34.2 0.571 35.442 1.723 ;
     RECT  39.348 0.571 40.05 1.723 ;
     RECT  44.496 0.571 45.81 1.723 ;
     RECT  49.608 0.571 50.274 1.723 ;
     RECT  54.756 0.571 55.35 1.723 ;
     RECT  59.904 0.571 60.498 1.723 ;
     RECT  64.98 0.571 64.998 1.723 ;
     RECT  70.128 0.571 70.758 1.723 ;
     RECT  71.928 0.571 71.946 1.723 ;
     RECT  85.5 0.571 86.166 1.723 ;
     RECT  87.264 0.571 87.282 1.723 ;
     RECT  90.648 0.619 91.242 1.723 ;
     RECT  95.76 0.571 96.354 1.723 ;
     RECT  97.56 0.571 97.578 1.723 ;
     RECT  101.484 0.571 101.502 1.723 ;
     RECT  106.596 0.571 107.19 1.723 ;
     RECT  111.168 0.571 111.798 1.723 ;
     RECT  116.928 0.571 117.522 1.723 ;
     RECT  122.004 0.571 122.022 1.723 ;
     RECT  127.152 0.571 127.17 1.723 ;
     RECT  132.264 0.571 132.282 1.723 ;
     RECT  133.416 0.571 133.434 1.723 ;
     RECT  137.376 0.091 137.394 1.723 ;
     RECT  139.14 0.091 139.158 1.723 ;
     RECT  142.524 0.091 143.694 1.723 ;
     RECT  147.636 0.523 148.374 1.723 ;
     RECT  149.472 0.091 149.49 1.723 ;
     RECT  153.36 0.091 153.378 1.723 ;
     RECT  154.548 0.091 154.566 1.723 ;
     RECT  158.472 0.091 158.49 1.723 ;
     RECT  159.66 0.091 159.678 1.723 ;
     RECT  2.304 0.139 3.006 2.101 ;
     RECT  4.356 1.723 7.11 2.143 ;
     RECT  7.992 1.723 12.258 2.143 ;
     RECT  59.904 1.723 61.65 2.143 ;
     RECT  62.388 1.723 66.186 2.143 ;
     RECT  79.632 1.723 82.71 2.143 ;
     RECT  83.556 1.723 84.006 2.143 ;
     RECT  90.648 1.723 93.618 2.143 ;
     RECT  94.356 1.723 94.986 2.143 ;
     RECT  110.34 1.723 110.358 2.143 ;
     RECT  111.168 1.723 113.562 2.143 ;
     RECT  120.6 1.723 121.158 2.143 ;
     RECT  122.004 1.723 123.714 2.143 ;
     RECT  125.748 1.723 126.234 2.143 ;
     RECT  127.152 1.723 130.77 2.143 ;
     RECT  131.508 1.723 131.526 2.143 ;
     RECT  132.264 1.723 135.918 2.143 ;
     RECT  151.488 1.723 152.478 2.191 ;
     RECT  153.36 1.723 157.014 2.191 ;
     RECT  4.356 2.143 12.258 2.227 ;
     RECT  23.976 1.723 25.686 2.255 ;
     RECT  90.648 2.143 94.986 2.255 ;
     RECT  142.524 1.723 144.81 2.255 ;
     RECT  2.304 2.101 3.366 2.263 ;
     RECT  26.424 1.723 26.874 2.263 ;
     RECT  84.744 1.723 84.762 2.263 ;
     RECT  85.5 1.723 87.282 2.263 ;
     RECT  100.728 1.723 100.746 2.263 ;
     RECT  101.484 1.723 103.842 2.263 ;
     RECT  141.768 1.723 141.786 2.263 ;
     RECT  142.524 2.255 143.37 2.263 ;
     RECT  4.284 2.227 12.258 2.335 ;
     RECT  2.304 2.263 3.438 2.371 ;
     RECT  4.212 2.335 12.258 2.371 ;
     RECT  13.104 1.723 15.426 2.371 ;
     RECT  16.236 1.723 17.334 2.371 ;
     RECT  18.252 1.723 21.87 2.371 ;
     RECT  22.608 1.723 23.094 2.371 ;
     RECT  23.976 2.255 25.542 2.371 ;
     RECT  26.316 2.263 26.874 2.371 ;
     RECT  27.72 1.723 32.058 2.371 ;
     RECT  32.796 1.723 33.354 2.371 ;
     RECT  34.2 1.723 37.89 2.371 ;
     RECT  38.628 1.723 41.742 2.371 ;
     RECT  42.48 1.723 43.614 2.371 ;
     RECT  44.496 1.723 46.818 2.371 ;
     RECT  47.592 1.723 48.87 2.371 ;
     RECT  49.608 1.723 51.462 2.371 ;
     RECT  52.2 1.723 53.226 2.371 ;
     RECT  53.964 1.723 53.982 2.371 ;
     RECT  54.756 1.723 58.374 2.371 ;
     RECT  59.112 1.723 59.13 2.371 ;
     RECT  59.904 2.143 66.186 2.371 ;
     RECT  66.924 1.723 69.282 2.371 ;
     RECT  70.128 1.723 73.098 2.371 ;
     RECT  73.836 1.723 74.502 2.371 ;
     RECT  75.24 0.571 76.41 2.371 ;
     RECT  77.184 1.723 78.894 2.371 ;
     RECT  79.632 2.143 84.006 2.371 ;
     RECT  84.744 2.263 87.282 2.371 ;
     RECT  88.092 1.723 89.082 2.371 ;
     RECT  89.892 1.723 89.91 2.371 ;
     RECT  90.648 2.255 93.366 2.371 ;
     RECT  94.14 2.255 94.986 2.371 ;
     RECT  95.76 1.723 99.99 2.371 ;
     RECT  100.728 2.263 103.842 2.371 ;
     RECT  104.58 1.723 105.714 2.371 ;
     RECT  106.596 1.723 108.378 2.371 ;
     RECT  109.116 1.723 109.602 2.371 ;
     RECT  110.34 2.143 113.562 2.371 ;
     RECT  114.3 1.723 114.786 2.371 ;
     RECT  115.524 1.723 116.154 2.371 ;
     RECT  116.928 1.723 118.638 2.371 ;
     RECT  119.376 1.723 119.862 2.371 ;
     RECT  120.6 2.143 123.714 2.371 ;
     RECT  124.452 1.723 125.01 2.371 ;
     RECT  125.748 2.143 130.77 2.371 ;
     RECT  131.508 2.143 135.918 2.371 ;
     RECT  136.656 1.723 139.734 2.371 ;
     RECT  140.472 1.723 140.994 2.371 ;
     RECT  141.768 2.263 143.37 2.371 ;
     RECT  144.108 2.255 144.81 2.371 ;
     RECT  145.62 1.723 146.826 2.371 ;
     RECT  147.636 1.723 150.714 2.371 ;
     RECT  151.488 2.191 157.014 2.371 ;
     RECT  157.752 1.723 160.326 2.371 ;
     RECT  2.304 2.371 25.542 2.489 ;
     RECT  26.316 2.371 93.366 2.489 ;
     RECT  94.14 2.371 143.37 2.489 ;
     RECT  144.108 2.371 160.434 2.641 ;
     RECT  15.408 2.489 25.542 3.145 ;
     RECT  26.316 2.489 27.342 3.145 ;
     RECT  92.268 2.489 93.366 3.145 ;
     RECT  109.656 2.489 143.37 3.145 ;
     RECT  144.108 2.641 160.758 3.145 ;
     RECT  92.268 3.145 93.402 3.181 ;
     RECT  94.14 2.489 96.606 3.181 ;
     RECT  15.408 3.145 27.342 3.271 ;
     RECT  28.116 2.489 49.842 3.271 ;
     RECT  56.415 2.489 63.234 3.307 ;
     RECT  63.972 2.489 67.77 3.307 ;
     RECT  68.508 2.489 83.697 3.343 ;
     RECT  84.492 2.489 91.53 3.343 ;
     RECT  2.304 2.489 14.67 3.379 ;
     RECT  15.408 3.271 49.842 3.379 ;
     RECT  56.415 3.307 67.77 3.379 ;
     RECT  68.508 3.343 91.53 3.379 ;
     RECT  92.268 3.181 96.606 3.379 ;
     RECT  97.344 2.489 101.718 3.379 ;
     RECT  102.456 2.489 108.846 3.379 ;
     RECT  109.656 3.145 160.758 3.379 ;
     RECT  53.208 2.489 55.602 3.415 ;
     RECT  56.415 3.379 160.758 3.415 ;
     RECT  2.304 3.379 49.878 3.451 ;
     RECT  50.616 2.489 52.434 3.451 ;
     RECT  53.208 3.415 160.758 3.629 ;
     RECT  2.304 3.451 52.434 3.685 ;
     RECT  53.208 3.629 81.918 3.685 ;
     RECT  82.692 3.629 160.758 3.685 ;
     RECT  2.304 3.685 81.918 3.749 ;
     RECT  162.036 3.721 162.054 3.811 ;
     RECT  26.712 3.749 81.918 3.875 ;
     RECT  82.692 3.685 160.902 3.875 ;
     RECT  2.304 3.749 25.866 3.947 ;
     RECT  29.052 3.875 35.802 3.947 ;
     RECT  36.648 3.875 81.918 3.947 ;
     RECT  95.76 3.875 148.698 3.947 ;
     RECT  149.544 3.875 160.902 3.947 ;
     RECT  149.652 3.947 160.902 3.965 ;
     RECT  39.456 3.947 81.918 3.983 ;
     RECT  99.072 3.947 148.698 3.983 ;
     RECT  29.124 3.947 33.966 4.013 ;
     RECT  59.94 3.983 81.918 4.013 ;
     RECT  119.052 3.983 148.698 4.019 ;
     RECT  29.232 4.013 33.966 4.109 ;
     RECT  68.22 4.013 81.918 4.109 ;
     RECT  119.052 4.019 146.106 4.109 ;
     RECT  149.832 3.965 160.902 4.117 ;
     RECT  161.82 3.811 162.054 4.117 ;
     RECT  36.648 3.947 38.718 4.145 ;
     RECT  108.612 3.983 118.098 4.145 ;
     RECT  2.304 3.947 25.83 4.157 ;
     RECT  39.456 3.983 41.418 4.157 ;
     RECT  42.192 3.983 58.842 4.157 ;
     RECT  59.94 4.013 67.497 4.157 ;
     RECT  68.22 4.109 72.954 4.157 ;
     RECT  99.072 3.983 107.55 4.157 ;
     RECT  122.832 4.109 146.106 4.157 ;
     RECT  149.832 4.117 162.054 4.157 ;
     RECT  119.052 4.109 122.094 4.168 ;
     RECT  82.692 3.875 94.986 4.181 ;
     RECT  142.596 4.157 146.106 4.181 ;
     RECT  147.168 4.019 148.698 4.181 ;
     RECT  149.832 4.157 159.297 4.181 ;
     RECT  2.304 4.157 14.094 4.289 ;
     RECT  14.868 4.157 16.614 4.289 ;
     RECT  32.652 4.109 33.966 4.289 ;
     RECT  63.576 4.157 65.394 4.289 ;
     RECT  71.1 4.157 72.954 4.289 ;
     RECT  73.692 4.109 81.918 4.289 ;
     RECT  87.804 4.181 94.986 4.289 ;
     RECT  129.996 4.157 134.262 4.289 ;
     RECT  140.328 4.157 141.786 4.289 ;
     RECT  160.02 4.157 162.054 4.289 ;
     RECT  2.304 4.289 11.538 4.379 ;
     RECT  15.084 4.289 16.614 4.379 ;
     RECT  39.564 4.157 41.418 4.379 ;
     RECT  73.872 4.289 75.726 4.379 ;
     RECT  76.572 4.289 81.918 4.379 ;
     RECT  92.196 4.289 94.986 4.379 ;
     RECT  122.832 4.157 128.646 4.379 ;
     RECT  135.072 4.157 139.374 4.379 ;
     RECT  9.288 4.379 10.098 4.415 ;
     RECT  15.084 4.379 15.21 4.415 ;
     RECT  29.232 4.109 31.734 4.415 ;
     RECT  34.776 3.947 35.802 4.415 ;
     RECT  42.624 4.157 58.842 4.415 ;
     RECT  63.9 4.289 65.394 4.415 ;
     RECT  71.28 4.289 72.954 4.415 ;
     RECT  76.572 4.379 79.434 4.415 ;
     RECT  80.424 4.379 81.846 4.415 ;
     RECT  92.196 4.379 92.358 4.415 ;
     RECT  95.76 3.947 98.082 4.415 ;
     RECT  99.396 4.157 107.55 4.415 ;
     RECT  119.052 4.168 122.058 4.415 ;
     RECT  122.832 4.379 122.922 4.415 ;
     RECT  123.696 4.379 128.646 4.415 ;
     RECT  133.236 4.289 134.262 4.415 ;
     RECT  136.872 4.379 139.374 4.415 ;
     RECT  142.596 4.181 145.998 4.415 ;
     RECT  147.168 4.181 148.554 4.415 ;
     RECT  149.904 4.181 159.297 4.415 ;
     RECT  133.452 4.415 134.262 4.451 ;
     RECT  82.692 4.181 86.994 4.459 ;
     RECT  93.168 4.379 94.986 4.487 ;
     RECT  142.596 4.415 145.782 4.487 ;
     RECT  90.288 4.289 91.35 4.493 ;
     RECT  26.712 3.875 28.278 4.507 ;
     RECT  17.676 4.157 25.83 4.523 ;
     RECT  95.76 4.415 97.074 4.523 ;
     RECT  142.596 4.487 143.478 4.523 ;
     RECT  82.656 4.459 86.994 4.531 ;
     RECT  59.94 4.157 62.514 4.541 ;
     RECT  138.528 4.415 139.374 4.541 ;
     RECT  37.62 4.145 38.718 4.559 ;
     RECT  93.96 4.487 94.986 4.559 ;
     RECT  151.236 4.415 155.646 4.559 ;
     RECT  9.288 4.415 10.026 4.649 ;
     RECT  12.456 4.289 14.094 4.649 ;
     RECT  21.096 4.523 25.83 4.649 ;
     RECT  42.624 4.415 45.897 4.649 ;
     RECT  64.728 4.415 65.394 4.649 ;
     RECT  77.544 4.415 78.822 4.649 ;
     RECT  82.584 4.531 86.994 4.649 ;
     RECT  90.288 4.493 91.242 4.649 ;
     RECT  100.692 4.415 107.55 4.649 ;
     RECT  123.696 4.415 125.082 4.649 ;
     RECT  125.964 4.415 127.746 4.649 ;
     RECT  129.996 4.289 132.297 4.649 ;
     RECT  136.872 4.415 137.697 4.649 ;
     RECT  151.236 4.559 153.897 4.649 ;
     RECT  156.744 4.415 159.297 4.649 ;
     RECT  46.62 4.415 58.842 4.685 ;
     RECT  59.94 4.541 60.138 4.685 ;
     RECT  66.132 4.157 67.497 4.685 ;
     RECT  80.424 4.415 81.198 4.685 ;
     RECT  102.528 4.649 107.55 4.685 ;
     RECT  108.612 4.145 116.097 4.685 ;
     RECT  116.82 4.145 118.098 4.685 ;
     RECT  119.052 4.415 119.07 4.685 ;
     RECT  80.424 4.685 81.09 4.691 ;
     RECT  26.604 4.507 28.278 4.721 ;
     RECT  48.384 4.685 58.842 4.721 ;
     RECT  27.684 4.721 28.278 4.765 ;
     RECT  29.232 4.415 30.438 4.765 ;
     RECT  104.724 4.685 105.642 4.793 ;
     RECT  119.844 4.415 122.058 4.793 ;
     RECT  32.796 4.289 33.966 4.801 ;
     RECT  34.776 4.415 35.298 4.801 ;
     RECT  37.764 4.559 38.718 4.801 ;
     RECT  66.996 4.685 67.497 4.801 ;
     RECT  68.22 4.157 70.326 4.801 ;
     RECT  106.416 4.685 107.55 4.801 ;
     RECT  117.9 4.685 118.098 4.801 ;
     RECT  17.676 4.523 19.062 4.829 ;
     RECT  26.604 4.721 26.946 4.829 ;
     RECT  9.468 4.649 10.026 4.919 ;
     RECT  27.684 4.765 30.438 4.919 ;
     RECT  48.384 4.721 58.05 4.919 ;
     RECT  83.415 4.649 86.994 4.919 ;
     RECT  100.692 4.649 101.322 4.919 ;
     RECT  144.216 4.487 145.782 4.919 ;
     RECT  48.384 4.919 53.658 4.955 ;
     RECT  54.396 4.919 58.05 4.955 ;
     RECT  71.28 4.415 71.478 4.955 ;
     RECT  161.316 4.289 162.054 5.035 ;
     RECT  11.16 4.379 11.538 5.071 ;
     RECT  31.392 4.415 31.734 5.071 ;
     RECT  32.796 4.801 35.298 5.071 ;
     RECT  64.944 4.649 65.394 5.071 ;
     RECT  66.132 4.685 66.15 5.071 ;
     RECT  71.28 4.955 71.298 5.071 ;
     RECT  72.36 4.415 72.954 5.071 ;
     RECT  73.872 4.379 74.358 5.071 ;
     RECT  86.904 4.919 86.994 5.071 ;
     RECT  87.804 4.289 89.514 5.071 ;
     RECT  90.288 4.649 90.306 5.071 ;
     RECT  99.396 4.415 99.954 5.071 ;
     RECT  117.9 4.801 118.17 5.071 ;
     RECT  138.744 4.541 139.374 5.071 ;
     RECT  140.904 4.289 141.786 5.071 ;
     RECT  142.596 4.523 143.19 5.071 ;
     RECT  160.02 4.289 160.47 5.071 ;
     RECT  161.316 5.035 162.522 5.071 ;
     RECT  94.032 4.559 94.986 5.161 ;
     RECT  95.76 4.523 95.814 5.161 ;
     RECT  140.904 5.071 143.19 5.161 ;
     RECT  163.584 5.035 163.602 5.189 ;
     RECT  17.784 4.829 19.062 5.341 ;
     RECT  19.8 4.523 19.818 5.341 ;
     RECT  25.056 4.649 25.83 5.341 ;
     RECT  26.604 4.829 26.766 5.341 ;
     RECT  31.392 5.071 35.298 5.341 ;
     RECT  60.12 4.685 60.138 5.341 ;
     RECT  60.984 4.541 62.514 5.341 ;
     RECT  72.36 5.071 74.358 5.341 ;
     RECT  75.348 4.379 75.726 5.341 ;
     RECT  78.015 4.649 78.822 5.341 ;
     RECT  91.116 4.649 91.242 5.341 ;
     RECT  92.268 4.415 92.358 5.341 ;
     RECT  98.028 4.415 98.082 5.341 ;
     RECT  98.892 5.071 99.954 5.341 ;
     RECT  113.688 4.685 116.097 5.341 ;
     RECT  116.82 4.685 117.162 5.341 ;
     RECT  126.216 4.649 127.746 5.341 ;
     RECT  128.484 4.415 128.646 5.341 ;
     RECT  144.324 4.919 145.782 5.341 ;
     RECT  147.168 4.415 148.497 5.341 ;
     RECT  154.692 4.559 155.646 5.341 ;
     RECT  160.02 5.071 162.81 5.341 ;
     RECT  140.76 5.161 143.19 5.431 ;
     RECT  154.692 5.341 156.042 5.431 ;
     RECT  157.212 4.649 159.297 5.431 ;
     RECT  78.015 5.341 79.11 5.459 ;
     RECT  160.02 5.341 163.494 5.459 ;
     RECT  37.764 4.801 38.754 5.539 ;
     RECT  54.504 4.955 58.05 5.539 ;
     RECT  82.584 4.649 82.602 5.539 ;
     RECT  96.588 4.523 97.074 5.539 ;
     RECT  98.028 5.341 99.954 5.539 ;
     RECT  138.744 5.071 139.662 5.539 ;
     RECT  154.692 5.431 159.297 5.539 ;
     RECT  160.02 5.459 162.054 5.539 ;
     RECT  144.324 5.341 146.286 5.575 ;
     RECT  147.168 5.341 148.554 5.575 ;
     RECT  2.304 4.379 8.55 5.611 ;
     RECT  9.468 4.919 9.702 5.611 ;
     RECT  11.16 5.071 11.61 5.611 ;
     RECT  12.456 4.649 12.474 5.611 ;
     RECT  13.215 4.649 14.094 5.611 ;
     RECT  15.084 4.415 15.102 5.611 ;
     RECT  15.984 4.379 16.614 5.611 ;
     RECT  17.784 5.341 19.818 5.611 ;
     RECT  21.096 4.649 24.297 5.611 ;
     RECT  31.392 5.341 35.694 5.611 ;
     RECT  36.648 4.145 36.666 5.611 ;
     RECT  37.656 5.539 38.754 5.611 ;
     RECT  39.816 4.379 41.382 5.611 ;
     RECT  42.984 4.649 45.897 5.611 ;
     RECT  46.836 4.685 47.574 5.611 ;
     RECT  54.504 5.539 58.158 5.611 ;
     RECT  59.04 4.801 59.058 5.611 ;
     RECT  60.12 5.341 62.514 5.611 ;
     RECT  63.9 4.415 63.918 5.611 ;
     RECT  64.944 5.071 66.15 5.611 ;
     RECT  66.996 4.801 70.326 5.611 ;
     RECT  71.1 5.071 71.298 5.611 ;
     RECT  72.36 5.341 75.726 5.611 ;
     RECT  76.572 4.415 76.77 5.611 ;
     RECT  78.015 5.459 78.678 5.611 ;
     RECT  80.46 4.691 81.09 5.611 ;
     RECT  82.26 5.539 82.602 5.611 ;
     RECT  86.904 5.071 90.306 5.611 ;
     RECT  91.116 5.341 92.358 5.611 ;
     RECT  93.168 4.487 93.186 5.611 ;
     RECT  94.032 5.161 95.814 5.611 ;
     RECT  96.588 5.539 99.954 5.611 ;
     RECT  101.16 4.919 101.322 5.611 ;
     RECT  102.528 4.685 103.662 5.611 ;
     RECT  105.015 4.793 105.642 5.611 ;
     RECT  106.416 4.801 107.658 5.611 ;
     RECT  108.612 4.685 111.15 5.611 ;
     RECT  111.96 4.685 112.878 5.611 ;
     RECT  113.688 5.341 117.162 5.611 ;
     RECT  117.9 5.071 118.602 5.611 ;
     RECT  119.844 4.793 120.15 5.611 ;
     RECT  120.888 4.793 122.058 5.611 ;
     RECT  122.904 4.415 122.922 5.611 ;
     RECT  124.164 4.649 125.082 5.611 ;
     RECT  126.216 5.341 128.646 5.611 ;
     RECT  130.428 4.649 132.297 5.611 ;
     RECT  133.452 4.451 134.118 5.611 ;
     RECT  135.072 4.379 136.026 5.611 ;
     RECT  137.232 4.649 137.697 5.611 ;
     RECT  138.744 5.539 139.842 5.611 ;
     RECT  140.76 5.431 143.37 5.611 ;
     RECT  144.324 5.575 148.554 5.611 ;
     RECT  149.904 4.415 150.498 5.611 ;
     RECT  151.596 4.649 153.897 5.611 ;
     RECT  59.868 5.611 62.514 5.809 ;
     RECT  63.36 5.611 64.098 5.809 ;
     RECT  140.652 5.611 143.37 5.809 ;
     RECT  144.324 5.611 153.954 5.809 ;
     RECT  48.996 4.955 53.658 5.845 ;
     RECT  2.304 5.611 9.702 5.881 ;
     RECT  10.944 5.611 24.297 5.881 ;
     RECT  25.056 5.341 26.766 5.881 ;
     RECT  27.684 4.919 30.33 5.881 ;
     RECT  31.392 5.611 38.754 5.881 ;
     RECT  39.564 5.611 47.898 5.881 ;
     RECT  48.888 5.845 53.658 5.881 ;
     RECT  54.504 5.611 59.058 5.881 ;
     RECT  59.868 5.809 64.098 5.881 ;
     RECT  64.944 5.611 71.298 5.881 ;
     RECT  72.36 5.611 76.77 5.881 ;
     RECT  77.58 5.611 78.678 5.881 ;
     RECT  79.452 5.611 82.602 5.881 ;
     RECT  83.415 4.919 86.022 5.881 ;
     RECT  86.904 5.611 93.186 5.881 ;
     RECT  94.032 5.611 100.314 5.881 ;
     RECT  101.16 5.611 104.094 5.881 ;
     RECT  105.015 5.611 111.15 5.881 ;
     RECT  111.96 5.611 117.162 5.881 ;
     RECT  117.9 5.611 118.962 5.881 ;
     RECT  119.844 5.611 125.082 5.881 ;
     RECT  126.216 5.611 136.026 5.881 ;
     RECT  136.98 5.611 139.842 5.881 ;
     RECT  140.652 5.809 153.954 5.881 ;
     RECT  154.692 5.539 162.054 5.881 ;
     RECT  2.304 5.881 71.406 5.971 ;
     RECT  72.144 5.881 78.678 5.971 ;
     RECT  79.452 5.881 139.842 5.971 ;
     RECT  140.58 5.881 162.054 5.971 ;
     RECT  2.304 5.971 78.678 5.999 ;
     RECT  162.828 5.459 163.494 5.999 ;
     RECT  2.304 5.999 26.73 6.035 ;
     RECT  27.612 5.999 78.57 6.035 ;
     RECT  79.452 5.971 162.054 6.035 ;
     RECT  55.548 6.035 56.934 6.071 ;
     RECT  57.708 6.035 78.57 6.071 ;
     RECT  79.812 6.035 109.206 6.071 ;
     RECT  131.184 6.035 135.486 6.071 ;
     RECT  136.224 6.035 145.242 6.071 ;
     RECT  2.304 6.035 9.342 6.179 ;
     RECT  10.26 6.035 21.474 6.179 ;
     RECT  57.708 6.071 71.55 6.227 ;
     RECT  10.26 6.179 20.25 6.305 ;
     RECT  21.096 6.179 21.474 6.305 ;
     RECT  27.612 6.035 31.086 6.305 ;
     RECT  31.896 6.035 32.958 6.305 ;
     RECT  33.768 6.035 41.418 6.305 ;
     RECT  42.192 6.035 54.81 6.305 ;
     RECT  55.548 6.071 56.754 6.305 ;
     RECT  57.708 6.227 61.905 6.305 ;
     RECT  62.712 6.227 71.55 6.305 ;
     RECT  79.812 6.071 102.942 6.305 ;
     RECT  103.752 6.071 109.206 6.305 ;
     RECT  117.648 6.035 130.374 6.305 ;
     RECT  131.184 6.071 133.578 6.305 ;
     RECT  136.224 6.071 139.914 6.305 ;
     RECT  140.76 6.071 145.242 6.305 ;
     RECT  146.016 6.035 154.602 6.305 ;
     RECT  155.556 6.035 162.054 6.305 ;
     RECT  162.936 5.999 163.494 6.305 ;
     RECT  10.44 6.305 11.97 6.341 ;
     RECT  14.616 6.305 20.25 6.341 ;
     RECT  22.248 6.035 26.73 6.341 ;
     RECT  33.768 6.305 38.286 6.341 ;
     RECT  53.1 6.305 54.81 6.341 ;
     RECT  65.232 6.305 70.254 6.341 ;
     RECT  72.288 6.071 78.57 6.341 ;
     RECT  2.34 6.179 9.342 6.377 ;
     RECT  42.408 6.305 52.326 6.377 ;
     RECT  14.616 6.341 16.398 6.413 ;
     RECT  33.768 6.341 38.214 6.413 ;
     RECT  42.408 6.377 51.534 6.413 ;
     RECT  72.288 6.341 78.534 6.413 ;
     RECT  92.7 6.305 100.926 6.413 ;
     RECT  109.98 6.035 112.05 6.413 ;
     RECT  136.224 6.305 138.042 6.413 ;
     RECT  157.536 6.305 162.054 6.421 ;
     RECT  163.152 6.305 163.494 6.421 ;
     RECT  44.028 6.413 51.534 6.497 ;
     RECT  57.816 6.305 61.905 6.497 ;
     RECT  65.232 6.341 67.734 6.497 ;
     RECT  78.015 6.413 78.534 6.497 ;
     RECT  79.992 6.305 86.886 6.497 ;
     RECT  94.215 6.413 100.926 6.497 ;
     RECT  109.98 6.413 111.942 6.497 ;
     RECT  115.056 6.035 116.91 6.497 ;
     RECT  117.756 6.305 124.038 6.497 ;
     RECT  136.296 6.413 138.042 6.497 ;
     RECT  146.16 6.305 150.174 6.497 ;
     RECT  157.536 6.421 162.162 6.497 ;
     RECT  22.248 6.341 25.326 6.845 ;
     RECT  3.564 6.377 9.342 6.893 ;
     RECT  10.44 6.341 11.898 6.893 ;
     RECT  14.616 6.413 16.362 6.893 ;
     RECT  17.136 6.341 20.25 6.893 ;
     RECT  21.204 6.305 21.474 6.893 ;
     RECT  22.248 6.845 23.382 6.893 ;
     RECT  32.04 6.305 32.958 6.893 ;
     RECT  33.768 6.413 35.586 6.893 ;
     RECT  42.408 6.413 43.254 6.893 ;
     RECT  44.028 6.497 50.31 6.893 ;
     RECT  51.156 6.497 51.534 6.893 ;
     RECT  53.1 6.341 54.774 6.893 ;
     RECT  57.816 6.497 61.794 6.893 ;
     RECT  62.712 6.305 63.054 6.893 ;
     RECT  63.936 6.305 64.422 6.893 ;
     RECT  65.232 6.497 66.978 6.893 ;
     RECT  68.544 6.341 70.254 6.893 ;
     RECT  79.992 6.497 82.998 6.893 ;
     RECT  84.096 6.497 86.886 6.893 ;
     RECT  94.464 6.497 99.09 6.893 ;
     RECT  99.828 6.497 100.926 6.893 ;
     RECT  103.752 6.305 107.262 6.893 ;
     RECT  108.036 6.305 109.206 6.893 ;
     RECT  109.98 6.497 110.394 6.893 ;
     RECT  112.932 6.035 114.246 6.893 ;
     RECT  115.056 6.497 115.434 6.893 ;
     RECT  117.756 6.497 120.798 6.893 ;
     RECT  124.776 6.305 130.374 6.893 ;
     RECT  131.184 6.305 132.822 6.893 ;
     RECT  133.56 6.305 133.578 6.893 ;
     RECT  3.564 6.893 4.986 7.421 ;
     RECT  6.732 6.893 6.75 7.421 ;
     RECT  8.028 6.893 9.342 7.421 ;
     RECT  10.728 6.893 11.898 7.421 ;
     RECT  12.852 6.305 13.878 7.421 ;
     RECT  14.616 6.893 15.822 7.421 ;
     RECT  17.136 6.893 18.342 7.421 ;
     RECT  19.548 6.893 20.25 7.421 ;
     RECT  24.156 6.845 25.326 7.421 ;
     RECT  26.136 6.341 26.73 7.421 ;
     RECT  27.792 6.305 29.862 7.421 ;
     RECT  33.768 6.893 34.974 7.421 ;
     RECT  36.324 6.413 38.214 7.421 ;
     RECT  39.06 6.305 41.418 7.421 ;
     RECT  42.408 6.893 42.678 7.421 ;
     RECT  44.028 6.893 49.05 7.421 ;
     RECT  51.156 6.893 51.174 7.421 ;
     RECT  52.308 6.377 52.326 7.421 ;
     RECT  53.1 6.893 54.27 7.421 ;
     RECT  55.656 6.305 56.754 7.421 ;
     RECT  57.816 6.893 60.714 7.421 ;
     RECT  65.232 6.893 66.438 7.421 ;
     RECT  67.716 6.497 67.734 7.421 ;
     RECT  70.236 6.893 70.254 7.421 ;
     RECT  71.064 6.305 71.55 7.421 ;
     RECT  72.288 6.413 73.422 7.421 ;
     RECT  74.196 6.413 77.274 7.421 ;
     RECT  78.228 6.497 78.534 7.421 ;
     RECT  79.992 6.893 81.27 7.421 ;
     RECT  82.332 6.893 82.35 7.421 ;
     RECT  84.096 6.893 85.698 7.421 ;
     RECT  86.868 6.893 86.886 7.421 ;
     RECT  87.624 6.305 90.702 7.421 ;
     RECT  91.476 6.305 91.962 7.421 ;
     RECT  92.7 6.413 93.366 7.421 ;
     RECT  94.644 6.893 97.758 7.421 ;
     RECT  99.072 6.893 99.09 7.421 ;
     RECT  100.908 6.893 100.926 7.421 ;
     RECT  101.664 6.305 102.942 7.421 ;
     RECT  103.752 6.893 106.686 7.421 ;
     RECT  108.036 6.893 108.702 7.421 ;
     RECT  109.98 6.893 109.998 7.421 ;
     RECT  111.204 6.497 111.942 7.421 ;
     RECT  112.932 6.893 113.778 7.421 ;
     RECT  115.056 6.893 115.074 7.421 ;
     RECT  116.568 6.497 116.91 7.421 ;
     RECT  117.756 6.893 118.206 7.421 ;
     RECT  119.484 6.893 119.502 7.421 ;
     RECT  120.78 6.893 120.798 7.421 ;
     RECT  121.572 6.497 124.038 7.421 ;
     RECT  124.776 6.893 129.87 7.421 ;
     RECT  131.184 6.893 132.354 7.421 ;
     RECT  134.352 6.071 135.486 7.421 ;
     RECT  135.036 7.421 135.486 7.997 ;
     RECT  137.664 6.497 138.042 7.997 ;
     RECT  138.852 6.305 139.914 7.997 ;
     RECT  146.16 6.497 147.69 7.997 ;
     RECT  148.428 6.497 150.174 7.997 ;
     RECT  151.812 6.305 154.602 7.997 ;
     RECT  159.48 6.497 162.162 7.997 ;
     RECT  163.152 6.421 163.602 7.997 ;
     RECT  2.34 6.377 2.79 8.381 ;
     RECT  3.564 7.421 3.726 8.429 ;
     RECT  79.992 7.421 80.55 8.477 ;
     RECT  2.34 8.381 2.358 8.525 ;
     RECT  3.708 8.429 3.726 8.525 ;
     RECT  10.728 7.421 11.466 8.525 ;
     RECT  17.136 7.421 17.694 8.525 ;
     RECT  21.204 6.893 21.222 8.525 ;
     RECT  22.248 6.893 22.986 8.525 ;
     RECT  27.792 7.421 28.17 8.525 ;
     RECT  30.96 6.305 31.086 8.525 ;
     RECT  32.04 6.893 32.598 8.525 ;
     RECT  38.196 7.421 38.214 8.525 ;
     RECT  39.06 7.421 39.078 8.525 ;
     RECT  42.408 7.421 42.426 8.525 ;
     RECT  44.028 7.421 44.046 8.525 ;
     RECT  47.916 7.421 48.474 8.525 ;
     RECT  53.1 7.421 53.766 8.525 ;
     RECT  57.816 7.421 58.806 8.525 ;
     RECT  62.712 6.893 62.73 8.525 ;
     RECT  63.936 6.893 63.954 8.525 ;
     RECT  68.544 6.893 68.562 8.525 ;
     RECT  72.972 7.421 72.99 8.525 ;
     RECT  74.196 7.421 74.79 8.525 ;
     RECT  78.228 7.421 78.246 8.525 ;
     RECT  80.532 8.477 80.55 8.525 ;
     RECT  84.096 7.421 84.978 8.525 ;
     RECT  88.956 7.421 88.974 8.525 ;
     RECT  90.144 7.421 90.162 8.525 ;
     RECT  94.644 7.421 95.31 8.525 ;
     RECT  99.828 6.893 99.846 8.525 ;
     RECT  103.752 7.421 103.77 8.525 ;
     RECT  104.94 7.421 105.57 8.525 ;
     RECT  111.204 7.421 111.222 8.525 ;
     RECT  112.932 7.421 112.95 8.525 ;
     RECT  116.568 7.421 116.586 8.525 ;
     RECT  121.572 7.421 121.59 8.525 ;
     RECT  125.496 7.421 126.558 8.525 ;
     RECT  131.184 7.421 131.202 8.525 ;
     RECT  135.036 7.997 135.054 8.525 ;
     RECT  136.296 6.497 136.89 8.525 ;
     RECT  137.664 7.997 137.682 8.525 ;
     RECT  138.852 7.997 139.518 8.525 ;
     RECT  140.868 6.305 143.298 8.525 ;
     RECT  144.144 6.305 145.242 8.525 ;
     RECT  146.16 7.997 147.15 8.525 ;
     RECT  148.428 7.997 149.13 8.525 ;
     RECT  150.912 6.305 150.93 8.525 ;
     RECT  151.812 7.997 153.558 8.525 ;
     RECT  155.556 6.305 156.69 8.525 ;
     RECT  157.536 6.497 158.706 8.525 ;
     RECT  159.48 7.997 161.946 8.525 ;
     RECT  163.152 7.997 163.17 8.525 ;
     RECT  164.34 4.963 164.358 8.525 ;
    LAYER M4 ;
     RECT  0.06 4.032 0.133 4.632 ;
     RECT  0.277 0.096 0.373 0.12 ;
     RECT  0.373 0.096 0.469 0.168 ;
     RECT  0.469 0.096 0.661 0.216 ;
     RECT  0.661 0.096 0.757 0.264 ;
     RECT  0.133 3.888 1.573 4.632 ;
     RECT  0.949 8.496 1.621 8.52 ;
     RECT  0.757 0.096 2.197 0.36 ;
     RECT  1.573 3.504 2.285 4.632 ;
     RECT  2.285 2.88 2.329 4.632 ;
     RECT  2.197 0.096 2.333 0.408 ;
     RECT  2.329 2.88 2.408 5.016 ;
     RECT  2.408 2.148 2.512 6.492 ;
     RECT  2.333 0.144 2.585 0.408 ;
     RECT  2.512 2.418 2.704 6.222 ;
     RECT  1.621 8.352 2.801 8.52 ;
     RECT  2.585 0.144 2.819 0.312 ;
     RECT  2.819 0.144 3.017 0.168 ;
     RECT  2.704 2.736 3.197 5.496 ;
     RECT  2.801 8.4 3.593 8.52 ;
     RECT  3.197 2.736 3.701 5.064 ;
     RECT  3.593 8.496 3.737 8.52 ;
     RECT  3.701 2.832 3.773 5.064 ;
     RECT  3.493 0.096 4.385 0.12 ;
     RECT  3.541 7.392 4.997 7.416 ;
     RECT  3.773 2.88 5.861 5.064 ;
     RECT  5.861 2.88 6.077 4.968 ;
     RECT  5.42 6.864 6.131 6.888 ;
     RECT  6.077 2.88 6.473 4.584 ;
     RECT  6.677 7.392 6.761 7.416 ;
     RECT  4.769 1.728 7.379 1.752 ;
     RECT  6.473 2.88 7.808 4.536 ;
     RECT  7.34 6.864 7.808 6.888 ;
     RECT  7.808 2.148 7.912 6.888 ;
     RECT  7.912 2.418 8.104 6.222 ;
     RECT  7.937 0.576 8.713 0.6 ;
     RECT  7.973 7.392 9.353 7.416 ;
     RECT  10.429 6.864 10.595 6.888 ;
     RECT  9.925 8.496 11.477 8.52 ;
     RECT  9.133 1.728 12.515 1.752 ;
     RECT  8.104 2.88 13.208 4.536 ;
     RECT  11.825 7.392 13.208 7.416 ;
     RECT  13.208 2.148 13.312 7.416 ;
     RECT  13.312 2.418 13.504 6.222 ;
     RECT  13.093 0.576 13.789 0.6 ;
     RECT  13.312 7.392 15.833 7.416 ;
     RECT  16.316 6.864 16.403 6.888 ;
     RECT  14.281 1.728 17.603 1.752 ;
     RECT  16.981 8.496 17.705 8.52 ;
     RECT  18.269 7.392 18.353 7.416 ;
     RECT  13.504 2.88 18.608 4.536 ;
     RECT  18.608 2.148 18.712 6.888 ;
     RECT  18.712 2.418 18.904 6.888 ;
     RECT  18.904 6.864 18.947 6.888 ;
     RECT  18.197 0.576 19.523 0.6 ;
     RECT  19.493 7.392 20.261 7.416 ;
     RECT  21.404 6.864 21.491 6.888 ;
     RECT  18.904 2.88 22.124 4.536 ;
     RECT  22.124 2.88 22.211 4.68 ;
     RECT  22.211 2.88 22.277 4.536 ;
     RECT  20.821 8.496 22.997 8.52 ;
     RECT  20.041 1.728 23.363 1.752 ;
     RECT  22.277 3.36 24.008 4.536 ;
     RECT  23.324 6.864 24.008 6.888 ;
     RECT  24.008 2.148 24.037 6.888 ;
     RECT  24.037 2.148 24.112 7.416 ;
     RECT  24.112 2.418 24.304 6.222 ;
     RECT  23.965 0.576 24.659 0.6 ;
     RECT  24.112 7.392 26.741 7.416 ;
     RECT  27.205 8.496 28.181 8.52 ;
     RECT  25.117 1.728 28.499 1.752 ;
     RECT  24.304 3.36 29.408 4.536 ;
     RECT  28.501 7.392 29.408 7.416 ;
     RECT  29.408 2.148 29.512 7.416 ;
     RECT  29.512 2.148 29.704 6.222 ;
     RECT  29.077 0.576 29.795 0.6 ;
     RECT  29.512 7.392 29.873 7.416 ;
     RECT  30.265 1.728 30.419 1.752 ;
     RECT  30.877 0.576 31.043 0.6 ;
     RECT  30.421 8.496 32.609 8.52 ;
     RECT  32.924 6.864 33.011 6.888 ;
     RECT  31.561 1.728 33.635 1.752 ;
     RECT  29.704 3.36 34.808 4.536 ;
     RECT  33.637 7.392 34.808 7.416 ;
     RECT  34.808 2.148 34.912 7.416 ;
     RECT  34.912 2.418 34.985 7.416 ;
     RECT  34.985 2.418 35.104 6.888 ;
     RECT  34.189 0.576 35.555 0.6 ;
     RECT  35.104 6.864 35.603 6.888 ;
     RECT  36.181 7.392 37.541 7.416 ;
     RECT  36.025 1.728 38.771 1.752 ;
     RECT  38.101 8.496 39.089 8.52 ;
     RECT  39.337 0.576 40.105 0.6 ;
     RECT  35.104 3.36 40.208 4.536 ;
     RECT  39.397 7.392 40.208 7.416 ;
     RECT  40.208 2.148 40.312 7.416 ;
     RECT  40.312 2.148 40.504 6.222 ;
     RECT  40.312 7.392 41.429 7.416 ;
     RECT  41.941 8.496 42.437 8.52 ;
     RECT  42.605 7.392 42.689 7.416 ;
     RECT  40.504 3.36 42.829 4.536 ;
     RECT  43.196 6.864 43.283 6.888 ;
     RECT  40.525 1.728 43.907 1.752 ;
     RECT  43.861 8.496 44.057 8.52 ;
     RECT  42.829 3.12 45.608 4.536 ;
     RECT  44.533 7.392 45.608 7.416 ;
     RECT  45.608 2.148 45.712 7.416 ;
     RECT  44.485 0.576 45.865 0.6 ;
     RECT  45.712 2.148 45.904 6.222 ;
     RECT  45.904 3.12 46.001 4.536 ;
     RECT  45.712 7.392 47.261 7.416 ;
     RECT  47.749 8.496 48.485 8.52 ;
     RECT  46.285 1.728 48.995 1.752 ;
     RECT  48.977 7.392 49.061 7.416 ;
     RECT  49.597 0.576 50.329 0.6 ;
     RECT  49.628 6.864 50.917 6.888 ;
     RECT  50.885 1.728 51.008 1.752 ;
     RECT  46.001 3.36 51.008 4.536 ;
     RECT  50.917 6.864 51.008 7.416 ;
     RECT  51.008 1.728 51.185 7.416 ;
     RECT  51.185 1.728 51.304 6.888 ;
     RECT  51.304 6.864 51.635 6.888 ;
     RECT  51.304 3.36 52.301 4.632 ;
     RECT  52.213 7.392 52.337 7.416 ;
     RECT  52.837 8.496 53.777 8.52 ;
     RECT  51.304 1.728 54.131 1.752 ;
     RECT  54.133 7.392 54.281 7.416 ;
     RECT  54.745 6.864 54.829 6.888 ;
     RECT  54.745 0.576 55.427 0.6 ;
     RECT  55.969 1.728 56.408 1.752 ;
     RECT  52.301 3.36 56.408 4.536 ;
     RECT  55.429 7.392 56.408 7.416 ;
     RECT  56.408 1.728 56.512 7.416 ;
     RECT  56.512 1.728 56.704 6.222 ;
     RECT  56.512 7.392 56.765 7.416 ;
     RECT  57.349 8.496 58.817 8.52 ;
     RECT  56.704 1.728 59.267 1.752 ;
     RECT  59.893 0.576 60.563 0.6 ;
     RECT  56.704 3.36 60.653 4.536 ;
     RECT  59.269 7.392 60.725 7.416 ;
     RECT  61.081 1.728 61.808 1.752 ;
     RECT  60.653 3.36 61.808 4.392 ;
     RECT  61.148 6.864 61.808 6.888 ;
     RECT  61.808 1.728 61.859 6.888 ;
     RECT  61.859 1.728 61.912 6.492 ;
     RECT  61.912 1.728 62.104 6.222 ;
     RECT  62.485 8.496 62.741 8.52 ;
     RECT  63.025 6.864 63.155 6.888 ;
     RECT  63.781 8.496 63.965 8.52 ;
     RECT  62.104 1.728 64.403 1.752 ;
     RECT  64.364 6.864 64.451 6.888 ;
     RECT  64.969 0.576 65.053 0.6 ;
     RECT  65.029 7.392 66.449 7.416 ;
     RECT  62.104 3.36 66.697 4.392 ;
     RECT  65.645 1.728 67.208 1.752 ;
     RECT  66.697 3.36 67.208 4.488 ;
     RECT  66.908 6.864 67.208 6.888 ;
     RECT  67.208 1.728 67.312 6.888 ;
     RECT  67.312 1.728 67.504 6.222 ;
     RECT  67.621 7.392 67.745 7.416 ;
     RECT  67.504 3.36 68.249 4.488 ;
     RECT  68.245 8.496 68.573 8.52 ;
     RECT  67.504 1.728 69.539 1.752 ;
     RECT  68.828 6.864 69.587 6.888 ;
     RECT  70.117 0.576 70.813 0.6 ;
     RECT  68.249 3.36 70.877 4.152 ;
     RECT  70.877 3.36 71.381 4.008 ;
     RECT  71.305 1.728 71.459 1.752 ;
     RECT  71.917 0.576 72.083 0.6 ;
     RECT  70.165 7.392 72.317 7.416 ;
     RECT  72.529 1.728 72.608 1.752 ;
     RECT  71.381 3.408 72.608 4.008 ;
     RECT  72.608 1.728 72.712 6.492 ;
     RECT  72.712 1.728 72.904 6.222 ;
     RECT  72.709 8.496 73.001 8.52 ;
     RECT  73.349 7.392 73.433 7.416 ;
     RECT  72.904 3.408 74.153 4.008 ;
     RECT  72.904 1.728 74.627 1.752 ;
     RECT  74.153 3.408 74.725 3.912 ;
     RECT  74.005 8.496 74.801 8.52 ;
     RECT  74.725 3.312 74.981 3.912 ;
     RECT  74.981 3.408 75.373 3.912 ;
     RECT  75.229 0.576 76.547 0.6 ;
     RECT  75.301 7.392 77.285 7.416 ;
     RECT  77.173 1.728 78.008 1.752 ;
     RECT  75.373 3.408 78.008 4.008 ;
     RECT  78.008 1.728 78.112 6.492 ;
     RECT  78.112 1.728 78.304 6.222 ;
     RECT  78.461 7.392 78.545 7.416 ;
     RECT  77.845 8.496 79.765 8.52 ;
     RECT  79.765 8.448 80.021 8.52 ;
     RECT  78.304 2.736 80.389 4.152 ;
     RECT  80.389 2.736 80.476 4.68 ;
     RECT  80.021 8.496 80.561 8.52 ;
     RECT  80.389 7.392 81.281 7.416 ;
     RECT  81.644 6.864 81.731 6.888 ;
     RECT  82.277 7.392 82.361 7.416 ;
     RECT  82.94 6.864 83.027 6.888 ;
     RECT  78.304 1.728 83.408 1.752 ;
     RECT  80.476 2.736 83.408 4.152 ;
     RECT  83.408 1.728 83.512 6.492 ;
     RECT  83.512 1.728 83.704 6.222 ;
     RECT  83.704 1.728 84.899 1.752 ;
     RECT  83.605 8.496 84.989 8.52 ;
     RECT  85.525 7.392 85.709 7.416 ;
     RECT  86.108 6.864 86.195 6.888 ;
     RECT  85.445 0.576 86.221 0.6 ;
     RECT  86.677 1.728 86.819 1.752 ;
     RECT  87.253 0.576 87.443 0.6 ;
     RECT  86.813 7.392 88.301 7.416 ;
     RECT  88.037 1.728 88.808 1.752 ;
     RECT  83.704 2.736 88.808 4.152 ;
     RECT  88.808 1.728 88.912 6.492 ;
     RECT  88.741 8.496 88.985 8.52 ;
     RECT  88.912 1.728 89.104 6.222 ;
     RECT  89.365 7.392 89.489 7.416 ;
     RECT  89.104 1.728 90.035 1.752 ;
     RECT  89.989 8.496 90.173 8.52 ;
     RECT  90.613 0.624 90.7 0.648 ;
     RECT  91.213 0.576 91.297 0.6 ;
     RECT  89.104 2.736 91.321 4.152 ;
     RECT  90.661 7.392 93.377 7.416 ;
     RECT  91.825 1.728 94.208 1.752 ;
     RECT  91.321 2.736 94.208 4.488 ;
     RECT  94.208 1.728 94.453 6.492 ;
     RECT  94.453 1.728 94.504 6.888 ;
     RECT  94.504 6.864 94.547 6.888 ;
     RECT  94.504 1.728 95.123 1.752 ;
     RECT  93.829 8.496 95.321 8.52 ;
     RECT  95.749 0.576 96.419 0.6 ;
     RECT  94.504 2.736 96.509 4.488 ;
     RECT  96.901 1.728 97.043 1.752 ;
     RECT  97.549 0.576 97.715 0.6 ;
     RECT  95.777 7.392 97.769 7.416 ;
     RECT  98.3 6.864 98.387 6.888 ;
     RECT  98.965 7.392 99.101 7.416 ;
     RECT  98.197 1.728 99.608 1.752 ;
     RECT  96.509 2.736 99.608 4.152 ;
     RECT  99.637 8.496 99.857 8.52 ;
     RECT  99.608 1.728 99.904 6.492 ;
     RECT  100.22 6.864 100.307 6.888 ;
     RECT  99.904 1.728 100.883 1.752 ;
     RECT  101.429 0.576 101.513 0.6 ;
     RECT  99.904 2.736 101.585 4.152 ;
     RECT  101.585 2.736 102.665 3.912 ;
     RECT  100.853 7.392 102.953 7.416 ;
     RECT  102.665 2.832 104.108 3.912 ;
     RECT  104.101 7.392 104.249 7.416 ;
     RECT  102.121 1.728 105.008 1.752 ;
     RECT  104.108 2.832 105.008 4.104 ;
     RECT  105.008 1.728 105.112 6.492 ;
     RECT  105.112 1.728 105.304 6.222 ;
     RECT  103.429 8.496 105.581 8.52 ;
     RECT  105.304 1.728 106.019 1.752 ;
     RECT  105.304 2.832 106.652 3.912 ;
     RECT  106.021 7.392 106.697 7.416 ;
     RECT  106.652 2.832 106.739 4.104 ;
     RECT  106.585 0.576 107.267 0.6 ;
     RECT  106.739 2.832 107.315 3.912 ;
     RECT  107.228 6.864 107.315 6.888 ;
     RECT  107.269 5.136 107.353 5.16 ;
     RECT  107.941 7.392 108.713 7.416 ;
     RECT  109.148 6.864 109.235 6.888 ;
     RECT  109.861 7.392 110.009 7.416 ;
     RECT  107.809 1.728 110.408 1.752 ;
     RECT  107.315 3.024 110.408 3.912 ;
     RECT  110.365 6.864 110.408 6.888 ;
     RECT  110.408 1.728 110.483 6.888 ;
     RECT  110.483 2.148 110.512 6.888 ;
     RECT  110.512 2.418 110.531 6.888 ;
     RECT  110.531 2.418 110.704 6.222 ;
     RECT  111.109 8.496 111.233 8.52 ;
     RECT  111.157 0.576 111.853 0.6 ;
     RECT  111.781 7.392 111.953 7.416 ;
     RECT  110.704 3.024 112.093 3.72 ;
     RECT  112.405 8.496 112.961 8.52 ;
     RECT  113.021 7.392 113.789 7.416 ;
     RECT  114.217 6.864 114.371 6.888 ;
     RECT  114.949 7.392 115.085 7.416 ;
     RECT  115.405 6.864 115.667 6.888 ;
     RECT  112.273 1.728 115.808 1.752 ;
     RECT  112.093 3.024 115.808 3.864 ;
     RECT  115.808 1.728 115.912 6.492 ;
     RECT  115.912 1.728 116.104 6.222 ;
     RECT  116.104 1.728 116.291 1.752 ;
     RECT  116.245 8.496 116.597 8.52 ;
     RECT  116.917 0.576 117.587 0.6 ;
     RECT  116.837 7.392 118.217 7.416 ;
     RECT  118.748 6.864 118.835 6.888 ;
     RECT  119.429 7.392 119.513 7.416 ;
     RECT  116.104 3.024 119.545 3.96 ;
     RECT  120.044 6.864 120.131 6.888 ;
     RECT  120.709 7.392 120.809 7.416 ;
     RECT  118.105 1.728 121.208 1.752 ;
     RECT  119.545 3.024 121.208 4.008 ;
     RECT  121.208 1.728 121.312 6.492 ;
     RECT  121.312 1.728 121.427 6.222 ;
     RECT  121.427 2.418 121.504 6.222 ;
     RECT  121.381 8.496 121.601 8.52 ;
     RECT  121.993 0.576 122.077 0.6 ;
     RECT  122.005 7.392 124.805 7.416 ;
     RECT  122.533 1.728 126.515 1.752 ;
     RECT  125.221 8.496 126.604 8.52 ;
     RECT  121.504 3.024 126.608 4.152 ;
     RECT  126.608 2.148 126.712 6.492 ;
     RECT  126.712 2.418 126.904 6.222 ;
     RECT  127.141 0.576 127.225 0.6 ;
     RECT  127.141 7.392 129.881 7.416 ;
     RECT  130.316 6.864 130.403 6.888 ;
     RECT  131.029 8.496 131.213 8.52 ;
     RECT  127.745 1.728 131.651 1.752 ;
     RECT  126.904 3.024 132.008 4.152 ;
     RECT  131.653 7.392 132.008 7.416 ;
     RECT  132.008 2.148 132.304 7.416 ;
     RECT  132.253 0.576 132.337 0.6 ;
     RECT  132.304 6.864 132.365 7.416 ;
     RECT  132.793 1.728 132.947 1.752 ;
     RECT  133.405 0.576 133.571 0.6 ;
     RECT  132.365 6.864 133.619 6.888 ;
     RECT  134.197 7.392 134.381 7.416 ;
     RECT  134.869 8.496 135.065 8.52 ;
     RECT  135.452 7.968 135.539 7.992 ;
     RECT  134.089 1.728 136.787 1.752 ;
     RECT  132.304 3.024 137.408 4.152 ;
     RECT  137.365 0.096 137.449 0.12 ;
     RECT  137.408 2.148 137.512 6.492 ;
     RECT  136.117 8.496 137.693 8.52 ;
     RECT  137.512 2.148 137.704 6.222 ;
     RECT  137.704 2.832 138.017 5.208 ;
     RECT  137.996 7.968 138.083 7.992 ;
     RECT  138.017 3.024 138.125 5.208 ;
     RECT  137.941 1.728 138.707 1.752 ;
     RECT  139.129 0.096 139.331 0.12 ;
     RECT  138.709 8.496 139.529 8.52 ;
     RECT  139.885 7.968 140.003 7.992 ;
     RECT  138.125 3.408 140.789 5.208 ;
     RECT  139.705 1.728 141.923 1.752 ;
     RECT  140.789 3.408 142.297 4.44 ;
     RECT  142.297 3.408 142.808 5.16 ;
     RECT  142.808 2.148 142.912 6.492 ;
     RECT  142.912 2.418 143.104 6.222 ;
     RECT  142.501 0.096 143.843 0.12 ;
     RECT  143.104 3.408 145.681 4.536 ;
     RECT  144.313 1.728 147.011 1.752 ;
     RECT  140.629 8.496 147.161 8.52 ;
     RECT  147.625 0.096 147.709 0.12 ;
     RECT  147.644 7.968 147.731 7.992 ;
     RECT  145.681 3.36 148.208 4.536 ;
     RECT  148.208 2.148 148.312 6.492 ;
     RECT  148.261 0.528 148.385 0.552 ;
     RECT  148.312 2.148 148.504 6.222 ;
     RECT  148.504 3.36 148.817 4.536 ;
     RECT  148.849 1.728 148.933 1.752 ;
     RECT  148.309 8.496 149.141 8.52 ;
     RECT  149.461 0.096 149.603 0.12 ;
     RECT  149.564 7.968 150.275 7.992 ;
     RECT  148.817 3.456 151.481 4.536 ;
     RECT  150.073 1.728 152.771 1.752 ;
     RECT  153.349 0.096 153.443 0.12 ;
     RECT  150.853 8.496 153.569 8.52 ;
     RECT  151.481 3.456 153.608 3.96 ;
     RECT  153.608 2.148 153.712 6.492 ;
     RECT  153.712 2.148 153.904 6.222 ;
     RECT  153.925 1.728 154.067 1.752 ;
     RECT  154.537 0.096 154.691 0.12 ;
     RECT  154.028 7.968 154.739 7.992 ;
     RECT  153.904 3.408 156.665 3.96 ;
     RECT  156.665 3.552 157.309 3.96 ;
     RECT  155.221 1.728 157.907 1.752 ;
     RECT  158.461 0.096 158.545 0.12 ;
     RECT  157.309 3.552 159.008 4.152 ;
     RECT  159.008 2.148 159.112 6.492 ;
     RECT  159.112 2.148 159.145 6.222 ;
     RECT  159.145 1.728 159.229 6.222 ;
     RECT  159.229 2.418 159.304 6.222 ;
     RECT  159.649 0.096 159.827 0.12 ;
     RECT  159.304 4.128 160.445 4.152 ;
     RECT  160.297 1.728 160.451 1.752 ;
     RECT  155.365 8.496 161.957 8.52 ;
     RECT  162.133 7.968 162.419 7.992 ;
     RECT  163.045 8.496 163.181 8.52 ;
     RECT  163.573 7.968 163.715 7.992 ;
     RECT  164.285 8.496 164.369 8.52 ;
    LAYER M5 ;
     RECT  0.288 0.016 160.44 0.131 ;
     RECT  0.384 0.131 2.904 0.179 ;
     RECT  0.48 0.179 2.904 0.227 ;
     RECT  0.576 0.227 2.904 0.371 ;
     RECT  148.272 0.131 148.92 0.563 ;
     RECT  4.128 0.131 136.776 0.611 ;
     RECT  88.08 0.611 90.648 0.659 ;
     RECT  4.128 0.611 7.368 1.763 ;
     RECT  9.264 0.611 12.504 1.763 ;
     RECT  14.4 0.611 17.592 1.763 ;
     RECT  20.16 0.611 23.352 1.763 ;
     RECT  25.248 0.611 28.488 1.763 ;
     RECT  30.384 0.611 30.408 1.763 ;
     RECT  31.68 0.611 33.624 1.763 ;
     RECT  36.144 0.611 38.76 1.763 ;
     RECT  40.656 0.611 43.896 1.763 ;
     RECT  46.416 0.611 48.984 1.763 ;
     RECT  50.928 0.611 54.12 1.763 ;
     RECT  56.016 0.611 59.256 1.763 ;
     RECT  61.152 0.611 64.392 1.763 ;
     RECT  65.664 0.611 69.528 1.763 ;
     RECT  71.424 0.611 71.448 1.763 ;
     RECT  72.672 0.611 74.616 1.763 ;
     RECT  77.184 0.611 84.888 1.763 ;
     RECT  86.784 0.611 86.808 1.763 ;
     RECT  88.08 0.659 90.024 1.763 ;
     RECT  91.92 0.611 95.112 1.763 ;
     RECT  97.008 0.611 97.032 1.763 ;
     RECT  98.304 0.611 100.872 1.763 ;
     RECT  102.144 0.611 106.008 1.763 ;
     RECT  107.904 0.611 110.472 1.763 ;
     RECT  112.416 0.611 116.28 1.763 ;
     RECT  118.176 0.611 121.416 1.763 ;
     RECT  122.64 0.611 126.504 1.763 ;
     RECT  127.776 0.611 131.64 1.763 ;
     RECT  132.912 0.611 132.936 1.763 ;
     RECT  134.208 0.611 136.776 1.763 ;
     RECT  138.048 0.131 138.696 1.763 ;
     RECT  139.968 0.131 141.912 1.763 ;
     RECT  144.432 0.131 147 1.763 ;
     RECT  148.896 0.563 148.92 1.763 ;
     RECT  150.192 0.131 152.76 1.763 ;
     RECT  154.032 0.131 154.056 1.763 ;
     RECT  155.328 0.131 157.896 1.763 ;
     RECT  160.416 0.131 160.44 1.763 ;
     RECT  72.672 1.763 72.912 2.137 ;
     RECT  110.4 1.763 110.472 2.137 ;
     RECT  159.168 0.131 159.192 2.137 ;
     RECT  7.8 2.137 7.92 2.151 ;
     RECT  13.2 2.137 13.32 2.151 ;
     RECT  18.6 2.137 18.72 2.151 ;
     RECT  24 2.137 24.12 2.151 ;
     RECT  34.8 2.137 34.92 2.151 ;
     RECT  110.4 2.137 110.52 2.151 ;
     RECT  121.2 1.763 121.416 2.151 ;
     RECT  126.6 2.137 126.72 2.151 ;
     RECT  142.8 2.137 142.92 2.151 ;
     RECT  159 2.137 159.192 2.151 ;
     RECT  137.4 2.137 137.712 2.821 ;
     RECT  1.584 0.371 2.904 2.915 ;
     RECT  4.128 1.763 4.152 2.963 ;
     RECT  24 2.151 24.312 3.397 ;
     RECT  105 1.763 105.312 3.397 ;
     RECT  107.28 2.821 107.304 3.397 ;
     RECT  126.6 2.151 126.912 3.397 ;
     RECT  137.4 2.821 137.976 3.397 ;
     RECT  1.584 2.915 2.808 3.443 ;
     RECT  102.576 3.013 102.6 3.443 ;
     RECT  1.584 3.443 2.712 3.539 ;
     RECT  51 1.763 51.312 3.637 ;
     RECT  74.688 3.541 74.712 3.683 ;
     RECT  126.6 3.397 127.848 3.683 ;
     RECT  0.576 0.371 0.6 3.877 ;
     RECT  0.144 3.877 0.6 4.019 ;
     RECT  23.376 3.397 24.312 4.019 ;
     RECT  0.144 4.019 0.168 4.067 ;
     RECT  104.16 3.397 105.312 4.115 ;
     RECT  106.704 3.397 107.304 4.115 ;
     RECT  50.688 3.637 51.312 4.117 ;
     RECT  142.8 2.151 143.112 4.117 ;
     RECT  50.688 4.117 52.248 4.163 ;
     RECT  53.52 3.397 53.544 4.163 ;
     RECT  137.4 3.397 138.504 4.547 ;
     RECT  51 4.163 52.248 4.643 ;
     RECT  22.176 4.213 22.2 4.691 ;
     RECT  80.4 4.117 80.424 4.691 ;
     RECT  5.088 3.781 5.112 5.027 ;
     RECT  107.28 4.115 107.304 5.171 ;
     RECT  142.464 4.117 143.112 5.171 ;
     RECT  137.4 4.547 137.832 5.219 ;
     RECT  2.4 3.539 2.712 6.489 ;
     RECT  61.8 1.763 62.112 6.489 ;
     RECT  83.4 1.763 83.712 6.489 ;
     RECT  110.4 2.151 110.712 6.489 ;
     RECT  137.4 5.219 137.712 6.489 ;
     RECT  142.8 5.171 143.112 6.489 ;
     RECT  148.2 2.137 148.512 6.489 ;
     RECT  153.6 2.137 153.912 6.489 ;
     RECT  159 2.151 159.312 6.489 ;
     RECT  2.4 6.489 2.52 6.503 ;
     RECT  61.8 6.489 61.92 6.503 ;
     RECT  72.6 2.137 72.912 6.503 ;
     RECT  78 1.763 78.312 6.503 ;
     RECT  83.4 6.489 83.52 6.503 ;
     RECT  88.8 1.763 89.112 6.503 ;
     RECT  94.2 1.763 94.512 6.503 ;
     RECT  99.6 1.763 99.912 6.503 ;
     RECT  105 4.115 105.312 6.503 ;
     RECT  115.8 1.763 116.112 6.503 ;
     RECT  121.2 2.151 121.512 6.503 ;
     RECT  126.6 3.683 126.912 6.503 ;
     RECT  137.4 6.489 137.52 6.503 ;
     RECT  142.8 6.489 142.92 6.503 ;
     RECT  148.2 6.489 148.32 6.503 ;
     RECT  153.6 6.489 153.72 6.503 ;
     RECT  159 6.489 159.12 6.503 ;
     RECT  7.8 2.151 8.112 6.853 ;
     RECT  18.6 2.151 18.912 6.853 ;
     RECT  24 4.019 24.312 6.853 ;
     RECT  34.8 2.151 35.112 6.853 ;
     RECT  51 4.643 51.312 6.853 ;
     RECT  61.8 6.503 61.848 6.853 ;
     RECT  67.2 1.763 67.512 6.853 ;
     RECT  132 2.137 132.312 6.853 ;
     RECT  5.472 6.853 6.12 7.381 ;
     RECT  7.392 6.853 8.112 7.381 ;
     RECT  13.2 2.151 13.512 7.381 ;
     RECT  16.368 6.853 16.392 7.381 ;
     RECT  18.6 6.853 18.936 7.381 ;
     RECT  23.376 6.853 24.312 7.381 ;
     RECT  29.4 2.137 29.712 7.381 ;
     RECT  32.976 6.853 33 7.381 ;
     RECT  34.8 6.853 35.592 7.381 ;
     RECT  40.2 2.137 40.512 7.381 ;
     RECT  43.248 6.853 43.272 7.381 ;
     RECT  45.6 2.137 45.912 7.381 ;
     RECT  49.68 6.853 51.624 7.381 ;
     RECT  54.768 6.853 54.792 7.381 ;
     RECT  56.4 1.763 56.712 7.381 ;
     RECT  61.2 6.853 61.848 7.381 ;
     RECT  64.416 6.853 64.44 7.381 ;
     RECT  66.96 6.853 67.512 7.381 ;
     RECT  68.88 6.853 69.576 7.381 ;
     RECT  81.696 6.853 81.72 7.381 ;
     RECT  82.992 6.853 83.016 7.381 ;
     RECT  86.16 6.853 86.184 7.381 ;
     RECT  98.352 6.853 98.376 7.381 ;
     RECT  100.272 6.853 100.296 7.381 ;
     RECT  107.28 6.853 107.304 7.381 ;
     RECT  109.2 6.853 109.224 7.381 ;
     RECT  110.4 6.489 110.52 7.381 ;
     RECT  114.336 6.853 114.36 7.381 ;
     RECT  115.632 6.853 115.656 7.381 ;
     RECT  118.8 6.853 118.824 7.381 ;
     RECT  120.096 6.853 120.12 7.381 ;
     RECT  130.368 6.853 130.392 7.381 ;
     RECT  132 6.853 133.608 7.381 ;
     RECT  1.632 8.341 1.656 8.389 ;
     RECT  80.4 7.381 83.016 8.437 ;
     RECT  1.632 8.389 2.28 8.485 ;
     RECT  3.552 7.381 9.336 8.485 ;
     RECT  10.56 6.853 10.584 8.485 ;
     RECT  11.856 7.381 16.392 8.485 ;
     RECT  18.288 7.381 20.232 8.485 ;
     RECT  21.456 6.853 21.48 8.485 ;
     RECT  23.376 7.381 26.616 8.485 ;
     RECT  28.512 7.381 29.832 8.485 ;
     RECT  32.976 7.381 37.512 8.485 ;
     RECT  39.408 7.381 41.352 8.485 ;
     RECT  42.624 7.381 43.272 8.485 ;
     RECT  44.544 7.381 47.112 8.485 ;
     RECT  49.008 7.381 52.248 8.485 ;
     RECT  54.144 7.381 56.712 8.485 ;
     RECT  59.28 7.381 61.848 8.485 ;
     RECT  63.12 6.853 63.144 8.485 ;
     RECT  64.416 7.381 67.656 8.485 ;
     RECT  68.88 7.381 72.12 8.485 ;
     RECT  73.392 7.381 73.416 8.485 ;
     RECT  75.312 7.381 77.256 8.485 ;
     RECT  78.48 7.381 78.504 8.485 ;
     RECT  79.776 8.437 83.016 8.485 ;
     RECT  85.536 7.381 88.104 8.485 ;
     RECT  89.376 7.381 89.4 8.485 ;
     RECT  90.672 7.381 93.24 8.485 ;
     RECT  94.512 6.853 94.536 8.485 ;
     RECT  95.808 7.381 99 8.485 ;
     RECT  100.272 7.381 102.84 8.485 ;
     RECT  104.112 7.381 104.136 8.485 ;
     RECT  106.032 7.381 110.52 8.485 ;
     RECT  111.792 7.381 111.816 8.485 ;
     RECT  113.04 7.381 115.656 8.485 ;
     RECT  116.88 7.381 120.744 8.485 ;
     RECT  122.016 7.381 124.632 8.485 ;
     RECT  127.152 7.381 130.392 8.485 ;
     RECT  131.664 7.381 134.232 8.485 ;
     RECT  135.504 7.957 135.528 8.485 ;
     RECT  138.048 7.957 138.072 8.485 ;
     RECT  139.968 7.957 139.992 8.485 ;
     RECT  147.696 7.957 147.72 8.485 ;
     RECT  149.616 7.957 150.264 8.485 ;
     RECT  154.08 7.957 154.728 8.485 ;
     RECT  162.384 7.957 162.408 8.485 ;
     RECT  163.68 7.957 163.704 8.485 ;
     RECT  0.96 8.485 164.328 8.592 ;
     RECT  2.952 0.131 3.456 0.132 ;
     RECT  3.576 0.131 4.08 0.132 ;
     RECT  136.824 0.131 137.328 0.132 ;
     RECT  137.448 0.131 138 0.132 ;
     RECT  138.744 0.131 139.248 0.132 ;
     RECT  139.368 0.131 139.92 0.132 ;
     RECT  147.048 0.131 147.6 0.132 ;
     RECT  147.72 0.131 148.224 0.132 ;
     RECT  148.968 0.131 149.52 0.132 ;
     RECT  149.64 0.131 150.144 0.132 ;
     RECT  152.808 0.131 153.36 0.132 ;
     RECT  153.48 0.131 153.984 0.132 ;
     RECT  154.104 0.131 154.608 0.132 ;
     RECT  154.728 0.131 155.28 0.132 ;
     RECT  157.944 0.131 158.448 0.132 ;
     RECT  158.568 0.131 159.12 0.132 ;
     RECT  159.24 0.131 159.744 0.132 ;
     RECT  159.864 0.131 160.368 0.132 ;
     RECT  2.904 0.132 4.128 2.915 ;
     RECT  136.776 0.132 138.048 1.763 ;
     RECT  138.696 0.132 139.968 1.763 ;
     RECT  147 0.132 148.272 0.563 ;
     RECT  148.92 0.132 150.192 1.763 ;
     RECT  152.76 0.132 154.032 1.763 ;
     RECT  154.056 0.132 155.328 1.763 ;
     RECT  157.896 0.132 159.168 1.763 ;
     RECT  159.192 0.132 160.416 1.763 ;
     RECT  0.6 0.371 1.584 3.539 ;
     RECT  7.368 0.611 9.264 1.763 ;
     RECT  12.504 0.611 14.4 1.763 ;
     RECT  17.592 0.611 20.16 1.763 ;
     RECT  23.352 0.611 25.248 1.763 ;
     RECT  28.488 0.611 30.384 1.763 ;
     RECT  30.408 0.611 31.68 1.763 ;
     RECT  33.624 0.611 36.144 1.763 ;
     RECT  38.76 0.611 40.656 1.763 ;
     RECT  45.6 0.611 46.416 1.763 ;
     RECT  64.392 0.611 65.664 1.763 ;
     RECT  71.448 0.611 72.672 1.763 ;
     RECT  86.808 0.611 88.08 1.763 ;
     RECT  90.648 0.611 91.92 0.659 ;
     RECT  97.032 0.611 98.304 1.763 ;
     RECT  100.872 0.611 102.144 1.763 ;
     RECT  110.472 0.611 110.52 2.137 ;
     RECT  121.416 0.611 122.64 1.763 ;
     RECT  126.504 0.611 127.776 1.763 ;
     RECT  131.64 0.611 132.912 1.763 ;
     RECT  132.936 0.611 134.208 1.763 ;
     RECT  7.8 1.763 8.112 2.137 ;
     RECT  13.2 1.763 13.512 2.137 ;
     RECT  18.6 1.763 18.912 2.137 ;
     RECT  24 1.763 24.312 2.137 ;
     RECT  29.4 1.763 29.712 2.137 ;
     RECT  34.8 1.763 35.112 2.137 ;
     RECT  40.2 1.763 40.512 2.137 ;
     RECT  45.6 1.763 45.912 2.137 ;
     RECT  72.6 1.763 72.672 2.137 ;
     RECT  102.576 1.763 102.6 3.013 ;
     RECT  121.416 1.763 121.512 2.151 ;
     RECT  126.6 1.763 126.912 2.137 ;
     RECT  132 1.763 132.312 2.137 ;
     RECT  137.4 1.763 137.976 2.137 ;
     RECT  153.6 1.763 153.912 2.137 ;
     RECT  159 1.763 159.168 2.137 ;
     RECT  159.192 1.763 159.312 2.151 ;
     RECT  7.92 2.137 8.112 2.151 ;
     RECT  13.32 2.137 13.512 2.151 ;
     RECT  18.72 2.137 18.912 2.151 ;
     RECT  24.12 2.137 24.312 2.151 ;
     RECT  34.92 2.137 35.112 2.151 ;
     RECT  126.72 2.137 126.912 2.151 ;
     RECT  137.712 2.137 137.976 2.821 ;
     RECT  2.808 2.915 4.128 2.963 ;
     RECT  105.312 3.397 106.704 4.115 ;
     RECT  52.248 4.117 53.52 4.163 ;
     RECT  61.92 6.489 62.112 6.503 ;
     RECT  110.52 6.489 110.712 7.381 ;
     RECT  61.848 6.503 62.112 6.853 ;
     RECT  72.6 6.503 72.912 7.381 ;
     RECT  78 6.503 78.312 7.381 ;
     RECT  88.8 6.503 89.112 7.381 ;
     RECT  94.2 6.503 94.512 7.381 ;
     RECT  99.6 6.503 99.912 6.853 ;
     RECT  115.8 6.503 116.112 6.853 ;
     RECT  121.2 6.503 121.512 6.853 ;
     RECT  6.12 6.853 7.392 7.381 ;
     RECT  61.848 6.853 63.12 8.485 ;
     RECT  63.144 6.853 64.416 8.485 ;
     RECT  67.512 6.853 68.88 7.381 ;
     RECT  81.72 6.853 82.992 7.381 ;
     RECT  98.376 6.853 100.272 7.381 ;
     RECT  109.224 6.853 110.4 7.381 ;
     RECT  114.36 6.853 115.632 7.381 ;
     RECT  115.656 6.853 116.112 7.381 ;
     RECT  118.824 6.853 120.096 7.381 ;
     RECT  120.12 6.853 121.512 7.381 ;
     RECT  9.336 7.381 10.56 8.485 ;
     RECT  10.584 7.381 11.856 8.485 ;
     RECT  20.232 7.381 21.456 8.485 ;
     RECT  41.352 7.381 42.624 8.485 ;
     RECT  43.272 7.381 44.544 8.485 ;
     RECT  67.656 7.381 68.88 8.485 ;
     RECT  72.12 7.381 73.392 8.485 ;
     RECT  77.256 7.381 78.48 8.485 ;
     RECT  88.104 7.381 89.376 8.485 ;
     RECT  89.4 7.381 90.672 8.485 ;
     RECT  93.24 7.381 94.512 8.485 ;
     RECT  94.536 7.381 95.808 8.485 ;
     RECT  99 7.381 100.272 8.485 ;
     RECT  102.84 7.381 104.112 8.485 ;
     RECT  110.52 7.381 111.792 8.485 ;
     RECT  111.816 7.381 113.04 8.485 ;
     RECT  115.656 7.381 116.88 8.485 ;
     RECT  120.744 7.381 122.016 8.485 ;
     RECT  130.392 7.381 131.664 8.485 ;
     RECT  134.232 7.957 135.504 8.485 ;
     RECT  162.408 7.957 163.68 8.485 ;
     RECT  2.28 8.389 3.552 8.485 ;
     RECT  78.504 8.437 79.776 8.485 ;
  END
END ot_engc_rr256
END LIBRARY
